FUNCTION "Gest Automatico" : VOID
TITLE =Gestione Ciclo Automatico
AUTHOR : MassimoZ
FAMILY : NovaSrl
VERSION : 0.1

BEGIN
NETWORK
TITLE =Condizioni per Ciclo

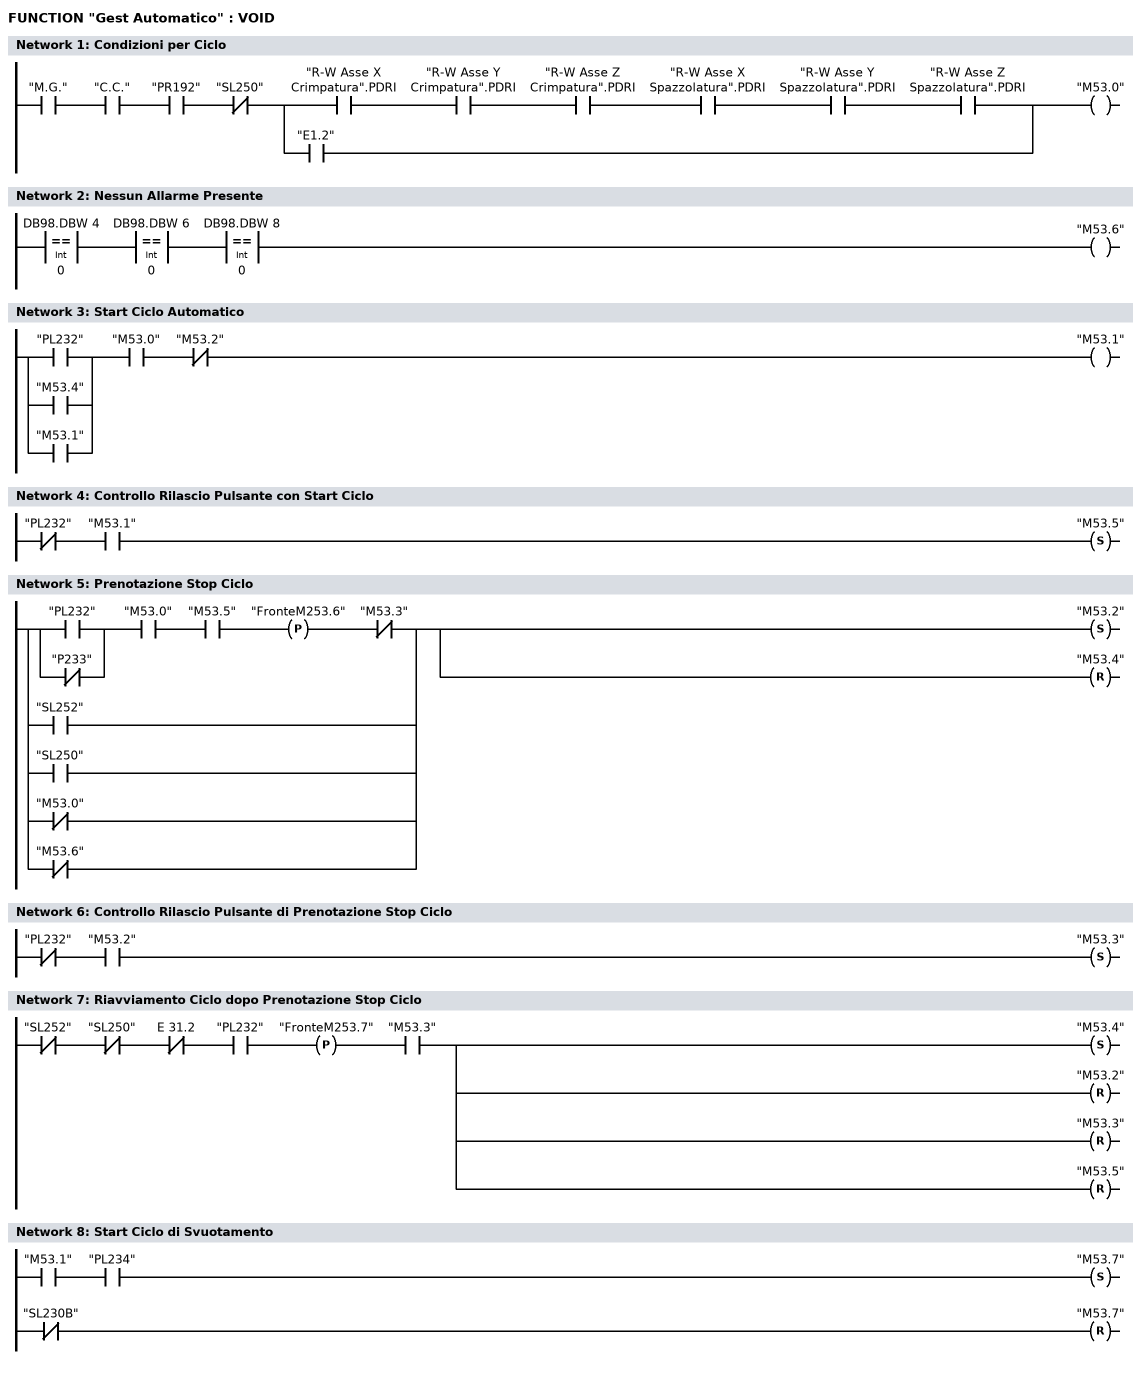
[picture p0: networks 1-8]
      U     "M.G.";
      U     "C.C.";
      U     "PR192";
      UN    "SL250";
      U(    ;
      U     "R-W Asse X Crimpatura".PDRI;
      U     "R-W Asse Y Crimpatura".PDRI;
      U     "R-W Asse Z Crimpatura".PDRI;
      U     "R-W Asse X Spazzolatura".PDRI;
      U     "R-W Asse Y Spazzolatura".PDRI;
      U     "R-W Asse Z Spazzolatura".PDRI;
      O     "E1.2";
      )     ;
      =     "M53.0";
NETWORK
TITLE =Nessun Allarme Presente

      U(    ;
      L     DB98.DBW    4;
      L     0;
      ==I   ;
      )     ;
      U(    ;
      L     DB98.DBW    6;
      L     0;
      ==I   ;
      )     ;
      U(    ;
      L     DB98.DBW    8;
      L     0;
      ==I   ;
      )     ;
      =     "M53.6";
NETWORK
TITLE =Start Ciclo Automatico

      U(    ;
      O     "PL232";
      O     "M53.4";
      O     "M53.1";
      )     ;
      U     "M53.0";
      UN    "M53.2";
      =     "M53.1";
NETWORK
TITLE =Controllo Rilascio Pulsante con Start Ciclo

      UN    "PL232";
      U     "M53.1";
      S     "M53.5";
NETWORK
TITLE =Prenotazione Stop Ciclo

      U(    ;
      O     "PL232";
      ON    "P233";
      )     ;
      U     "M53.0";
      U     "M53.5";
      FP    "FronteM253.6";
      UN    "M53.3";
      O     "SL252";
      O     "SL250";
      ON    "M53.0";
      ON    "M53.6";
      S     "M53.2";
      R     "M53.4";
NETWORK
TITLE =Controllo Rilascio Pulsante di Prenotazione Stop Ciclo

      UN    "PL232";
      U     "M53.2";
      S     "M53.3";
NETWORK
TITLE =Riavviamento Ciclo dopo Prenotazione Stop Ciclo

      UN    "SL252";
      UN    "SL250";
      UN    E     31.2;
      U     "PL232";
      FP    "FronteM253.7";
      U     "M53.3";
      S     "M53.4";
      R     "M53.2";
      R     "M53.3";
      R     "M53.5";
NETWORK
TITLE =Start Ciclo di Svuotamento

      U     "M53.1";
      U     "PL234";
      S     "M53.7";
      UN    "SL230B";
      R     "M53.7";
      NOP   0;
NETWORK
TITLE ======== Ciclo Automatico =======

NETWORK
TITLE =Presenza Pezzo in Entrata Zona Crimpatura

      U(    ;
      UN    "SL230";
      U     "SL230B";
      U     "FT183";
      L     S5T#1S500MS;
      SE    T     36;
      NOP   0;
      NOP   0;
      NOP   0;
      U     T     36;
      )     ;
      L     S5T#4S;
      SA    T     37;
      NOP   0;
      NOP   0;
      NOP   0;
      U     T     37;
      =     "M54.0";
NETWORK
TITLE =Presenza Pezzo Zona Crimpatura

      U(    ;
      UN    "SL230";
      U     "SL230B";
      U     "FT186";
      L     S5T#800MS;
      SE    T     38;
      NOP   0;
      NOP   0;
      NOP   0;
      U     T     38;
      )     ;
      L     S5T#500MS;
      SA    T     39;
      NOP   0;
      NOP   0;
      NOP   0;
      U     T     39;
      =     "M54.1";
NETWORK
TITLE =Presenza Pezzo Zona Spazzolatura

      U(    ;
      UN    "SL230";
      U     "SL230B";
      U     "FT190";
      L     S5T#800MS;
      SE    T     40;
      NOP   0;
      NOP   0;
      NOP   0;
      U     T     40;
      )     ;
      L     S5T#500MS;
      SA    T     54;
      NOP   0;
      NOP   0;
      NOP   0;
      U     T     54;
      =     "M54.2";
NETWORK
TITLE =Com Aut Start Motore Nastro Trasportatore

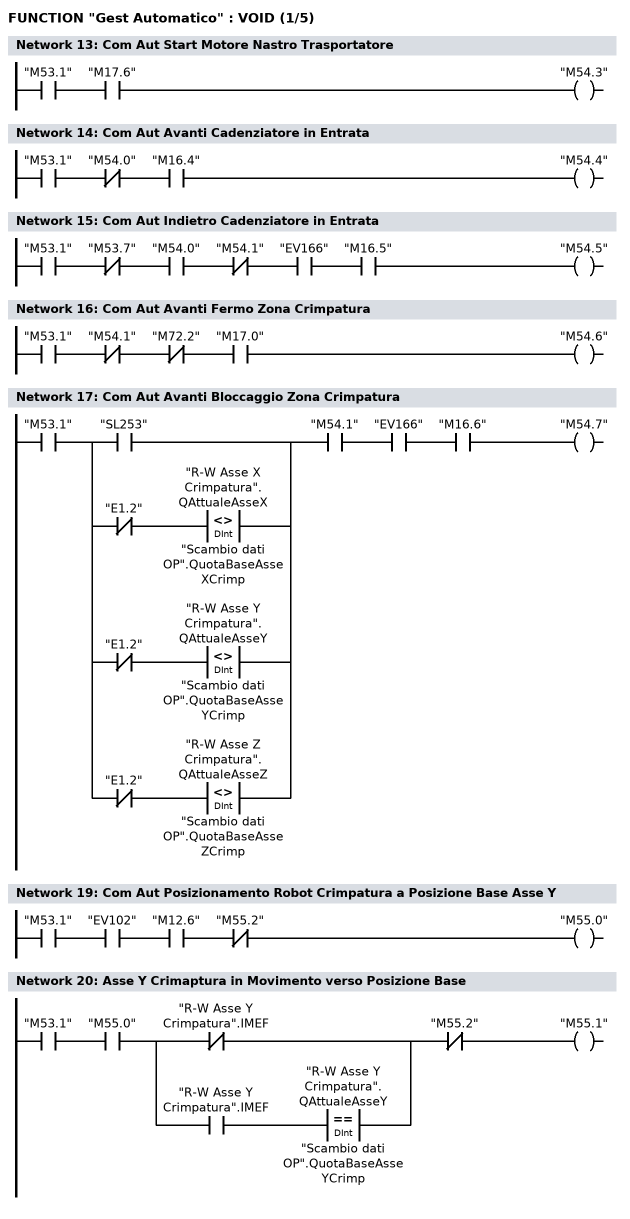
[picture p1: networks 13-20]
      U     "M53.1";
      U     "M17.6";
      =     "M54.3";
NETWORK
TITLE =Com Aut Avanti Cadenziatore in Entrata

      U     "M53.1";
      UN    "M54.0";
      U     "M16.4";
      =     "M54.4";
NETWORK
TITLE =Com Aut Indietro Cadenziatore in Entrata

      U     "M53.1";
      UN    "M53.7";
      U     "M54.0";
      UN    "M54.1";
      U     "EV166";
      U     "M16.5";
      =     "M54.5";
NETWORK
TITLE =Com Aut Avanti Fermo Zona Crimpatura

      U     "M53.1";
      UN    "M54.1";
      UN    "M72.2";
      U     "M17.0";
      =     "M54.6";
NETWORK
TITLE =Com Aut Avanti Bloccaggio Zona Crimpatura

      U     "M53.1";
      U(    ;
      O     "SL253";
      O     ;
      UN    "E1.2";
      U(    ;
      L     "R-W Asse X Crimpatura".QAttualeAsseX;
      L     "Scambio dati OP".QuotaBaseAsseXCrimp;
      <>D   ;
      )     ;
      O     ;
      UN    "E1.2";
      U(    ;
      L     "R-W Asse Y Crimpatura".QAttualeAsseY;
      L     "Scambio dati OP".QuotaBaseAsseYCrimp;
      <>D   ;
      )     ;
      O     ;
      UN    "E1.2";
      U(    ;
      L     "R-W Asse Z Crimpatura".QAttualeAsseZ;
      L     "Scambio dati OP".QuotaBaseAsseZCrimp;
      <>D   ;
      )     ;
      )     ;
      U     "M54.1";
      U     "EV166";
      U     "M16.6";
      =     "M54.7";
NETWORK
TITLE ======== Ciclo Automatico Crimpatura ========

NETWORK
TITLE =Com Aut Posizionamento Robot Crimpatura a Posizione Base Asse Y

      U     "M53.1";
      U     "EV102";
      U     "M12.6";
      UN    "M55.2";
      =     "M55.0";
NETWORK
TITLE =Asse Y Crimaptura in Movimento verso Posizione Base

      U     "M53.1";
      U     "M55.0";
      U(    ;
      ON    "R-W Asse Y Crimpatura".IMEF;
      O     ;
      U     "R-W Asse Y Crimpatura".IMEF;
      U(    ;
      L     "R-W Asse Y Crimpatura".QAttualeAsseY;
      L     "Scambio dati OP".QuotaBaseAsseYCrimp;
      ==D   ;
      )     ;
      )     ;
      UN    "M55.2";
      =     "M55.1";
NETWORK
TITLE =Asse Y Crimpatura Posizione Base Raggiunta

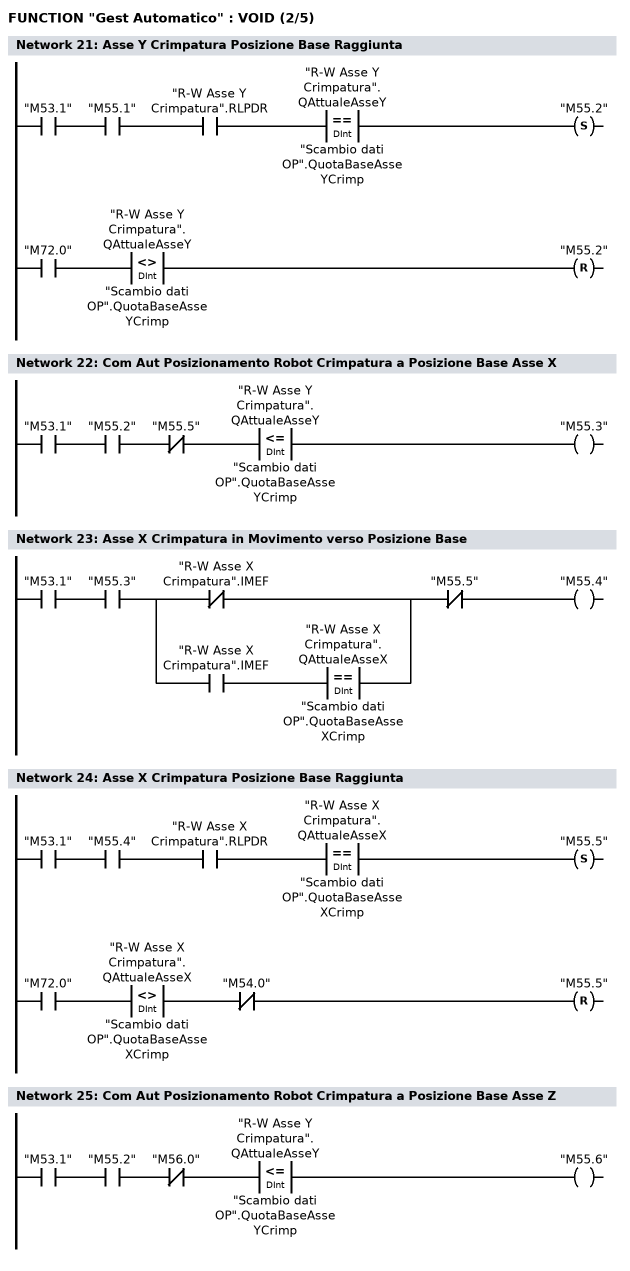
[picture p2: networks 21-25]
      U     "M53.1";
      U     "M55.1";
      U     "R-W Asse Y Crimpatura".RLPDR;
      U(    ;
      L     "R-W Asse Y Crimpatura".QAttualeAsseY;
      L     "Scambio dati OP".QuotaBaseAsseYCrimp;
      ==D   ;
      )     ;
      S     "M55.2";
      U     "M72.0";
      U(    ;
      L     "R-W Asse Y Crimpatura".QAttualeAsseY;
      L     "Scambio dati OP".QuotaBaseAsseYCrimp;
      <>D   ;
      )     ;
      R     "M55.2";
      NOP   0;
NETWORK
TITLE =Com Aut Posizionamento Robot Crimpatura a Posizione Base Asse X

      U     "M53.1";
      U     "M55.2";
      UN    "M55.5";
      U(    ;
      L     "R-W Asse Y Crimpatura".QAttualeAsseY;
      L     "Scambio dati OP".QuotaBaseAsseYCrimp;
      <=D   ;
      )     ;
      =     "M55.3";
NETWORK
TITLE =Asse X Crimpatura in Movimento verso Posizione Base

      U     "M53.1";
      U     "M55.3";
      U(    ;
      ON    "R-W Asse X Crimpatura".IMEF;
      O     ;
      U     "R-W Asse X Crimpatura".IMEF;
      U(    ;
      L     "R-W Asse X Crimpatura".QAttualeAsseX;
      L     "Scambio dati OP".QuotaBaseAsseXCrimp;
      ==D   ;
      )     ;
      )     ;
      UN    "M55.5";
      =     "M55.4";
NETWORK
TITLE =Asse X Crimpatura Posizione Base Raggiunta

      U     "M53.1";
      U     "M55.4";
      U     "R-W Asse X Crimpatura".RLPDR;
      U(    ;
      L     "R-W Asse X Crimpatura".QAttualeAsseX;
      L     "Scambio dati OP".QuotaBaseAsseXCrimp;
      ==D   ;
      )     ;
      S     "M55.5";
      U     "M72.0";
      U(    ;
      L     "R-W Asse X Crimpatura".QAttualeAsseX;
      L     "Scambio dati OP".QuotaBaseAsseXCrimp;
      <>D   ;
      )     ;
      UN    "M54.0";
      R     "M55.5";
      NOP   0;
NETWORK
TITLE =Com Aut Posizionamento Robot Crimpatura a Posizione Base Asse Z

      U     "M53.1";
      U     "M55.2";
      UN    "M56.0";
      U(    ;
      L     "R-W Asse Y Crimpatura".QAttualeAsseY;
      L     "Scambio dati OP".QuotaBaseAsseYCrimp;
      <=D   ;
      )     ;
      =     "M55.6";
NETWORK
TITLE =Asse Z Crimpatura in Movimento verso Posizione Base

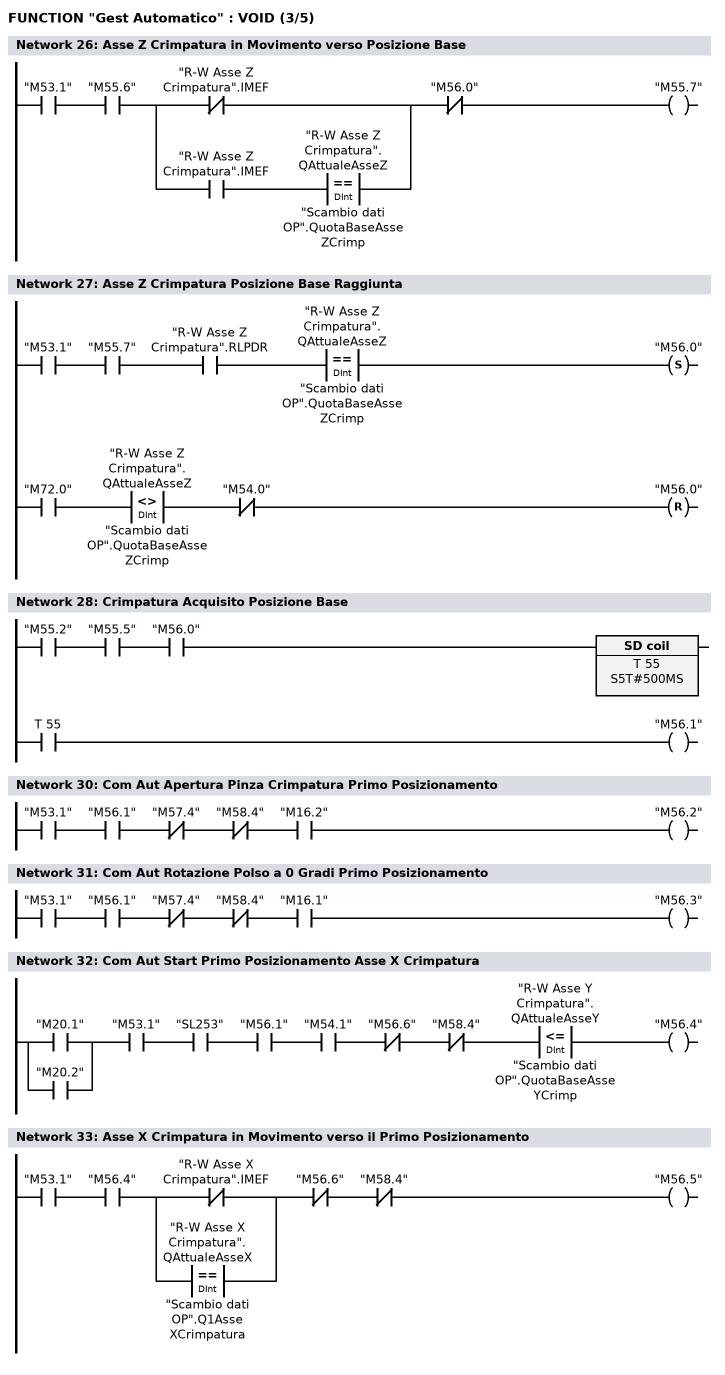
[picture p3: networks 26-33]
      U     "M53.1";
      U     "M55.6";
      U(    ;
      ON    "R-W Asse Z Crimpatura".IMEF;
      O     ;
      U     "R-W Asse Z Crimpatura".IMEF;
      U(    ;
      L     "R-W Asse Z Crimpatura".QAttualeAsseZ;
      L     "Scambio dati OP".QuotaBaseAsseZCrimp;
      ==D   ;
      )     ;
      )     ;
      UN    "M56.0";
      =     "M55.7";
NETWORK
TITLE =Asse Z Crimpatura Posizione Base Raggiunta

      U     "M53.1";
      U     "M55.7";
      U     "R-W Asse Z Crimpatura".RLPDR;
      U(    ;
      L     "R-W Asse Z Crimpatura".QAttualeAsseZ;
      L     "Scambio dati OP".QuotaBaseAsseZCrimp;
      ==D   ;
      )     ;
      S     "M56.0";
      U     "M72.0";
      U(    ;
      L     "R-W Asse Z Crimpatura".QAttualeAsseZ;
      L     "Scambio dati OP".QuotaBaseAsseZCrimp;
      <>D   ;
      )     ;
      UN    "M54.0";
      R     "M56.0";
      NOP   0;
NETWORK
TITLE =Crimpatura Acquisito Posizione Base

      U     "M55.2";
      U     "M55.5";
      U     "M56.0";
      L     S5T#500MS;
      SE    T     55;
      NOP   0;
      NOP   0;
      NOP   0;
      U     T     55;
      =     "M56.1";
NETWORK
TITLE ======== Primo Posizionamento Crimpatura =======

NETWORK
TITLE =Com Aut Apertura Pinza Crimpatura Primo Posizionamento

      U     "M53.1";
      U     "M56.1";
      UN    "M57.4";
      UN    "M58.4";
      U     "M16.2";
      =     "M56.2";
NETWORK
TITLE =Com Aut Rotazione Polso a 0 Gradi Primo Posizionamento

      U     "M53.1";
      U     "M56.1";
      UN    "M57.4";
      UN    "M58.4";
      U     "M16.1";
      =     "M56.3";
NETWORK
TITLE =Com Aut Start Primo Posizionamento Asse X Crimpatura

      U(    ;
      O     "M20.1";
      O     "M20.2";
      )     ;
      U     "M53.1";
      U     "SL253";
      U     "M56.1";
      U     "M54.1";
      UN    "M56.6";
      UN    "M58.4";
      U(    ;
      L     "R-W Asse Y Crimpatura".QAttualeAsseY;
      L     "Scambio dati OP".QuotaBaseAsseYCrimp;
      <=D   ;
      )     ;
      =     "M56.4";
NETWORK
TITLE =Asse X Crimpatura in Movimento verso il Primo Posizionamento

      U     "M53.1";
      U     "M56.4";
      U(    ;
      ON    "R-W Asse X Crimpatura".IMEF;
      O(    ;
      L     "R-W Asse X Crimpatura".QAttualeAsseX;
      L     "Scambio dati OP".Q1AsseXCrimpatura;
      ==D   ;
      )     ;
      )     ;
      UN    "M56.6";
      UN    "M58.4";
      =     "M56.5";
NETWORK
TITLE =Asse X Crimpatura Primo Posizionamento Raggiunto

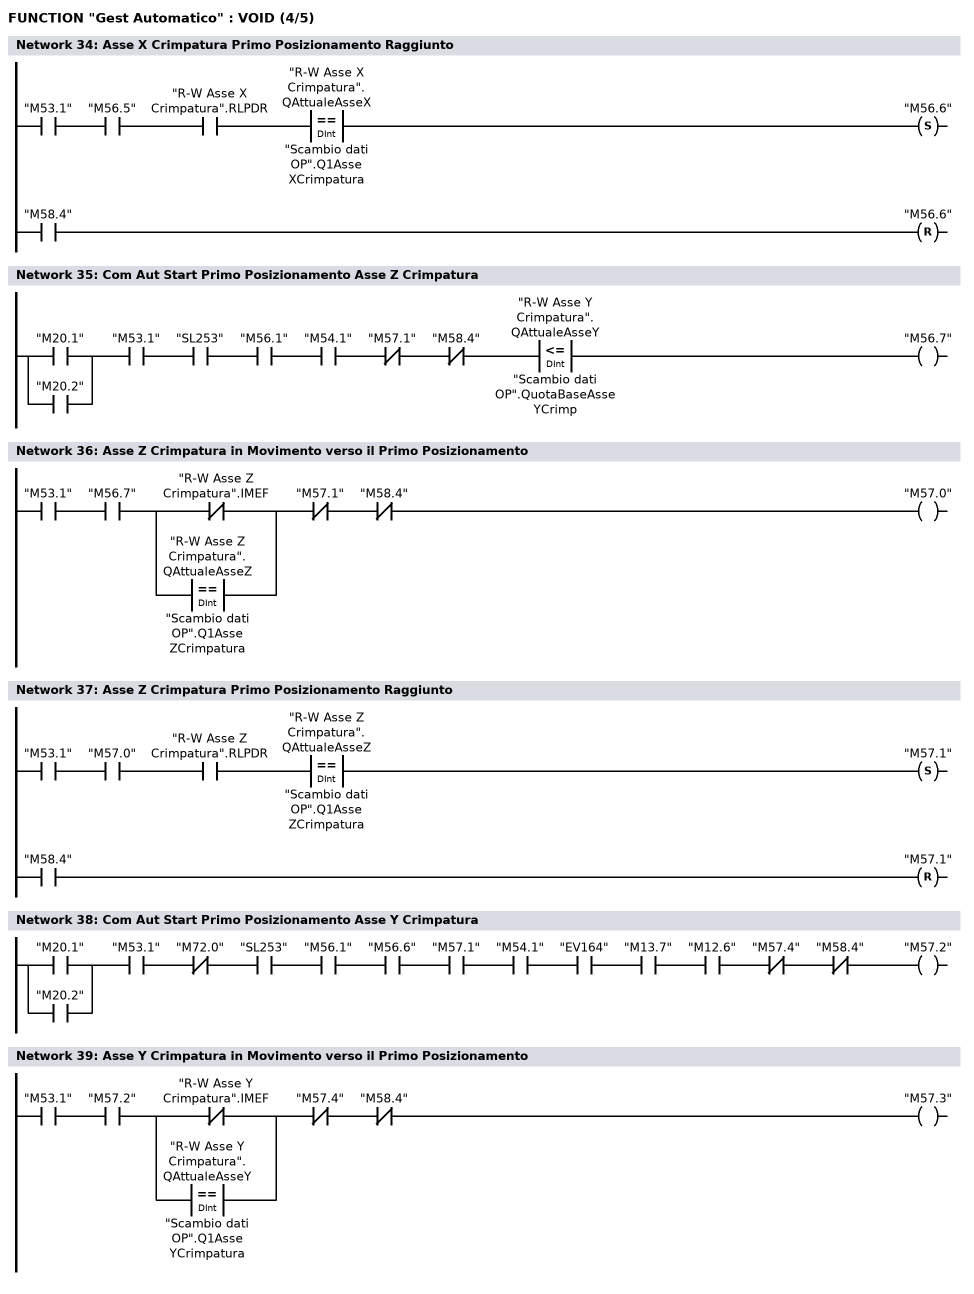
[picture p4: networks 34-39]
      U     "M53.1";
      U     "M56.5";
      U     "R-W Asse X Crimpatura".RLPDR;
      U(    ;
      L     "R-W Asse X Crimpatura".QAttualeAsseX;
      L     "Scambio dati OP".Q1AsseXCrimpatura;
      ==D   ;
      )     ;
      S     "M56.6";
      U     "M58.4";
      R     "M56.6";
      NOP   0;
NETWORK
TITLE =Com Aut Start Primo Posizionamento Asse Z Crimpatura

      U(    ;
      O     "M20.1";
      O     "M20.2";
      )     ;
      U     "M53.1";
      U     "SL253";
      U     "M56.1";
      U     "M54.1";
      UN    "M57.1";
      UN    "M58.4";
      U(    ;
      L     "R-W Asse Y Crimpatura".QAttualeAsseY;
      L     "Scambio dati OP".QuotaBaseAsseYCrimp;
      <=D   ;
      )     ;
      =     "M56.7";
NETWORK
TITLE =Asse Z Crimpatura in Movimento verso il Primo Posizionamento

      U     "M53.1";
      U     "M56.7";
      U(    ;
      ON    "R-W Asse Z Crimpatura".IMEF;
      O(    ;
      L     "R-W Asse Z Crimpatura".QAttualeAsseZ;
      L     "Scambio dati OP".Q1AsseZCrimpatura;
      ==D   ;
      )     ;
      )     ;
      UN    "M57.1";
      UN    "M58.4";
      =     "M57.0";
NETWORK
TITLE =Asse Z Crimpatura Primo Posizionamento Raggiunto

      U     "M53.1";
      U     "M57.0";
      U     "R-W Asse Z Crimpatura".RLPDR;
      U(    ;
      L     "R-W Asse Z Crimpatura".QAttualeAsseZ;
      L     "Scambio dati OP".Q1AsseZCrimpatura;
      ==D   ;
      )     ;
      S     "M57.1";
      U     "M58.4";
      R     "M57.1";
      NOP   0;
NETWORK
TITLE =Com Aut Start Primo Posizionamento Asse Y Crimpatura

      U(    ;
      O     "M20.1";
      O     "M20.2";
      )     ;
      U     "M53.1";
      UN    "M72.0";
      U     "SL253";
      U     "M56.1";
      U     "M56.6";
      U     "M57.1";
      U     "M54.1";
      U     "EV164";
      U     "M13.7";
      U     "M12.6";
      UN    "M57.4";
      UN    "M58.4";
      =     "M57.2";
NETWORK
TITLE =Asse Y Crimpatura in Movimento verso il Primo Posizionamento

      U     "M53.1";
      U     "M57.2";
      U(    ;
      ON    "R-W Asse Y Crimpatura".IMEF;
      O(    ;
      L     "R-W Asse Y Crimpatura".QAttualeAsseY;
      L     "Scambio dati OP".Q1AsseYCrimpatura;
      ==D   ;
      )     ;
      )     ;
      UN    "M57.4";
      UN    "M58.4";
      =     "M57.3";
NETWORK
TITLE =Asse Y Crimpatura Primo Posizionamento Raggiunto

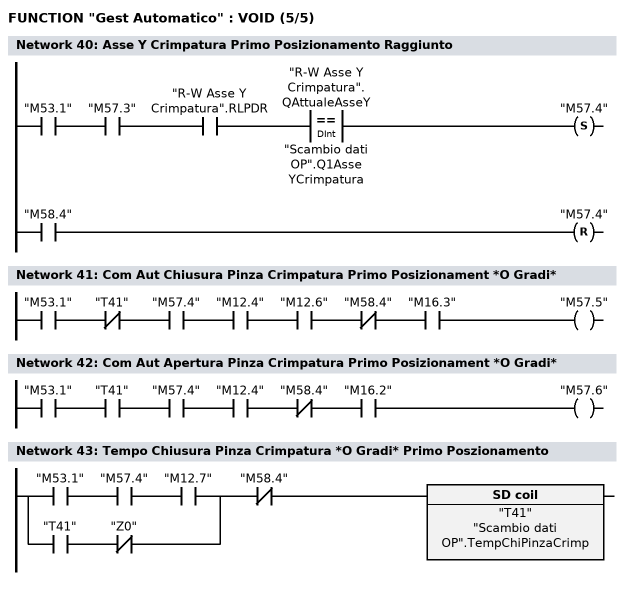
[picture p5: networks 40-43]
      U     "M53.1";
      U     "M57.3";
      U     "R-W Asse Y Crimpatura".RLPDR;
      U(    ;
      L     "R-W Asse Y Crimpatura".QAttualeAsseY;
      L     "Scambio dati OP".Q1AsseYCrimpatura;
      ==D   ;
      )     ;
      S     "M57.4";
      U     "M58.4";
      R     "M57.4";
      NOP   0;
NETWORK
TITLE =Com Aut Chiusura Pinza Crimpatura Primo Posizionament *O Gradi*

      U     "M53.1";
      UN    "T41";
      U     "M57.4";
      U     "M12.4";
      U     "M12.6";
      UN    "M58.4";
      U     "M16.3";
      =     "M57.5";
NETWORK
TITLE =Com Aut Apertura Pinza Crimpatura Primo Posizionament *O Gradi*

      U     "M53.1";
      U     "T41";
      U     "M57.4";
      U     "M12.4";
      UN    "M58.4";
      U     "M16.2";
      =     "M57.6";
NETWORK
TITLE =Tempo Chiusura Pinza Crimpatura *O Gradi* Primo Poszionamento

      U(    ;
      U     "M53.1";
      U     "M57.4";
      U     "M12.7";
      O     ;
      U     "T41";
      UN    "Z0";
      )     ;
      UN    "M58.4";
      L     "Scambio dati OP".TempChiPinzaCrimp;
      SE    "T41";
      NOP   0;
      NOP   0;
      NOP   0;
      NOP   0;
NETWORK
TITLE =Numero di Crimpate da Eseguire *O Gradi* Primo Posizionamento

      U     "EV103";
      U     "M57.5";
      U     "M12.4";
      UN    "M58.4";
      ZR    "Z0";
      BLD   101;
      U     "M57.2";
      L     "Scambio dati OP".NCrimp0Gradi;
      S     "Z0";
      U     "M58.4";
      R     "Z0";
      NOP   0;
      NOP   0;
      NOP   0;
NETWORK
TITLE =Com Aut Rotazione Polso a 45 Gradi Primo Posizionamento

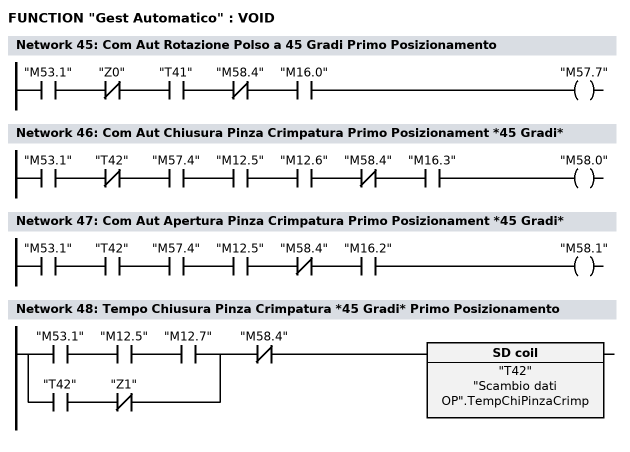
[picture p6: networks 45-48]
      U     "M53.1";
      UN    "Z0";
      U     "T41";
      UN    "M58.4";
      U     "M16.0";
      =     "M57.7";
NETWORK
TITLE =Com Aut Chiusura Pinza Crimpatura Primo Posizionament *45 Gradi*

      U     "M53.1";
      UN    "T42";
      U     "M57.4";
      U     "M12.5";
      U     "M12.6";
      UN    "M58.4";
      U     "M16.3";
      =     "M58.0";
NETWORK
TITLE =Com Aut Apertura Pinza Crimpatura Primo Posizionament *45 Gradi*

      U     "M53.1";
      U     "T42";
      U     "M57.4";
      U     "M12.5";
      UN    "M58.4";
      U     "M16.2";
      =     "M58.1";
NETWORK
TITLE =Tempo Chiusura Pinza Crimpatura *45 Gradi* Primo Posizionamento

      U(    ;
      U     "M53.1";
      U     "M12.5";
      U     "M12.7";
      O     ;
      U     "T42";
      UN    "Z1";
      )     ;
      UN    "M58.4";
      L     "Scambio dati OP".TempChiPinzaCrimp;
      SE    "T42";
      NOP   0;
      NOP   0;
      NOP   0;
      NOP   0;
NETWORK
TITLE =Numero di Crimpate da Eseguire *45 Gradi* Primo Posizionamento

      U     "EV103";
      U     "M58.0";
      U     "M12.5";
      UN    "M58.4";
      ZR    "Z1";
      BLD   101;
      U     "M57.2";
      L     "Scambio dati OP".NCrimp45Gradi;
      S     "Z1";
      U     "M58.4";
      R     "Z1";
      NOP   0;
      NOP   0;
      NOP   0;
NETWORK
TITLE =Com Aut Start Pos Base Asse Y Crimpatura dopo Prima Crimpatura

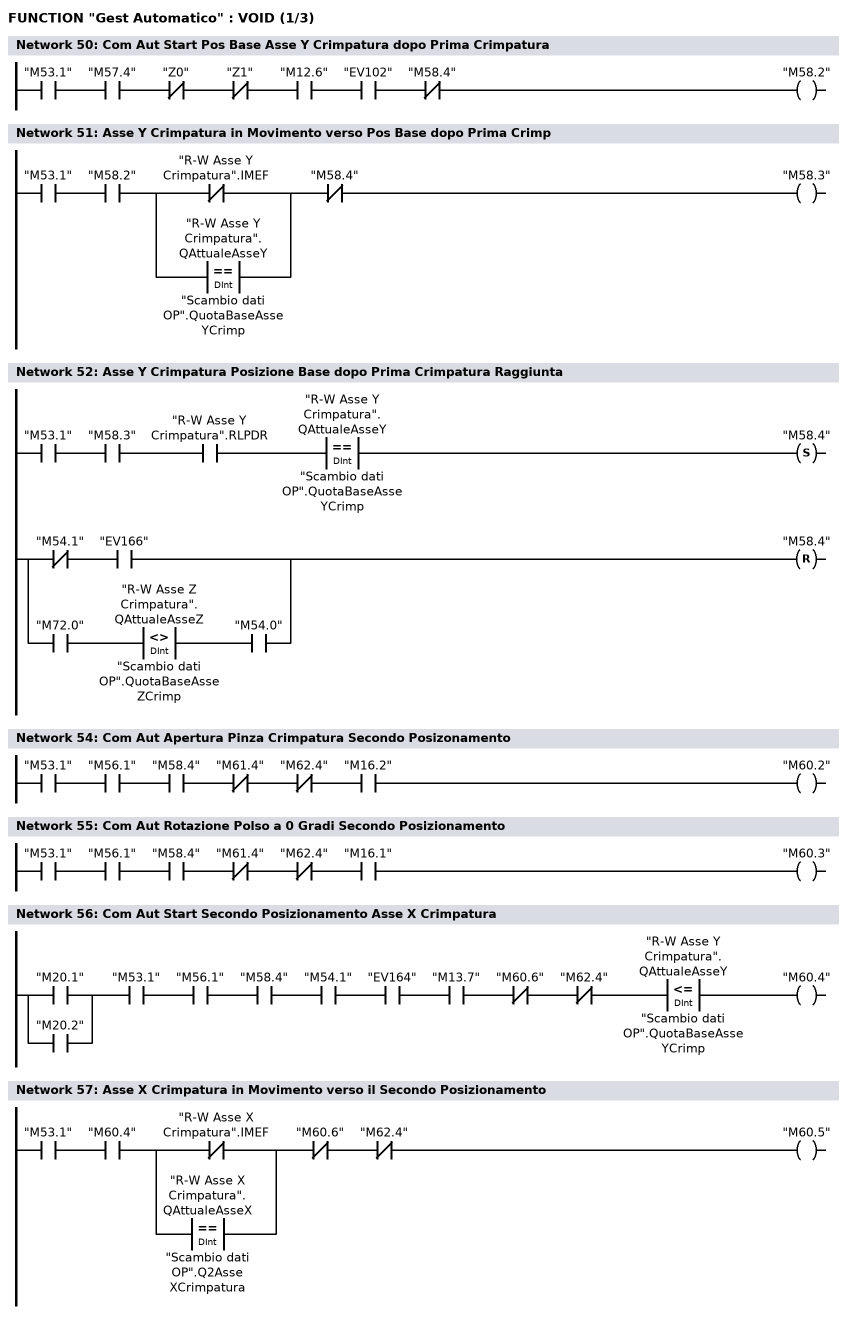
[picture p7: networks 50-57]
      U     "M53.1";
      U     "M57.4";
      UN    "Z0";
      UN    "Z1";
      U     "M12.6";
      U     "EV102";
      UN    "M58.4";
      =     "M58.2";
NETWORK
TITLE =Asse Y Crimpatura in Movimento verso Pos Base dopo Prima Crimp

      U     "M53.1";
      U     "M58.2";
      U(    ;
      ON    "R-W Asse Y Crimpatura".IMEF;
      O(    ;
      L     "R-W Asse Y Crimpatura".QAttualeAsseY;
      L     "Scambio dati OP".QuotaBaseAsseYCrimp;
      ==D   ;
      )     ;
      )     ;
      UN    "M58.4";
      =     "M58.3";
NETWORK
TITLE =Asse Y Crimpatura Posizione Base dopo Prima Crimpatura Raggiunta

      U     "M53.1";
      U     "M58.3";
      U     "R-W Asse Y Crimpatura".RLPDR;
      U(    ;
      L     "R-W Asse Y Crimpatura".QAttualeAsseY;
      L     "Scambio dati OP".QuotaBaseAsseYCrimp;
      ==D   ;
      )     ;
      S     "M58.4";
      U(    ;
      UN    "M54.1";
      U     "EV166";
      O     ;
      U     "M72.0";
      U(    ;
      L     "R-W Asse Z Crimpatura".QAttualeAsseZ;
      L     "Scambio dati OP".QuotaBaseAsseZCrimp;
      <>D   ;
      )     ;
      U     "M54.0";
      )     ;
      R     "M58.4";
      NOP   0;
NETWORK
TITLE ======== Secondo Posizionamento Crimpatura =======

NETWORK
TITLE =Com Aut Apertura Pinza Crimpatura Secondo Posizonamento

      U     "M53.1";
      U     "M56.1";
      U     "M58.4";
      UN    "M61.4";
      UN    "M62.4";
      U     "M16.2";
      =     "M60.2";
NETWORK
TITLE =Com Aut Rotazione Polso a 0 Gradi Secondo Posizionamento

      U     "M53.1";
      U     "M56.1";
      U     "M58.4";
      UN    "M61.4";
      UN    "M62.4";
      U     "M16.1";
      =     "M60.3";
NETWORK
TITLE =Com Aut Start Secondo Posizionamento Asse X Crimpatura

      U(    ;
      O     "M20.1";
      O     "M20.2";
      )     ;
      U     "M53.1";
      U     "M56.1";
      U     "M58.4";
      U     "M54.1";
      U     "EV164";
      U     "M13.7";
      UN    "M60.6";
      UN    "M62.4";
      U(    ;
      L     "R-W Asse Y Crimpatura".QAttualeAsseY;
      L     "Scambio dati OP".QuotaBaseAsseYCrimp;
      <=D   ;
      )     ;
      =     "M60.4";
NETWORK
TITLE =Asse X Crimpatura in Movimento verso il Secondo Posizionamento

      U     "M53.1";
      U     "M60.4";
      U(    ;
      ON    "R-W Asse X Crimpatura".IMEF;
      O(    ;
      L     "R-W Asse X Crimpatura".QAttualeAsseX;
      L     "Scambio dati OP".Q2AsseXCrimpatura;
      ==D   ;
      )     ;
      )     ;
      UN    "M60.6";
      UN    "M62.4";
      =     "M60.5";
NETWORK
TITLE =Asse X Crimpatura Secondo Posizionamento Raggiunto

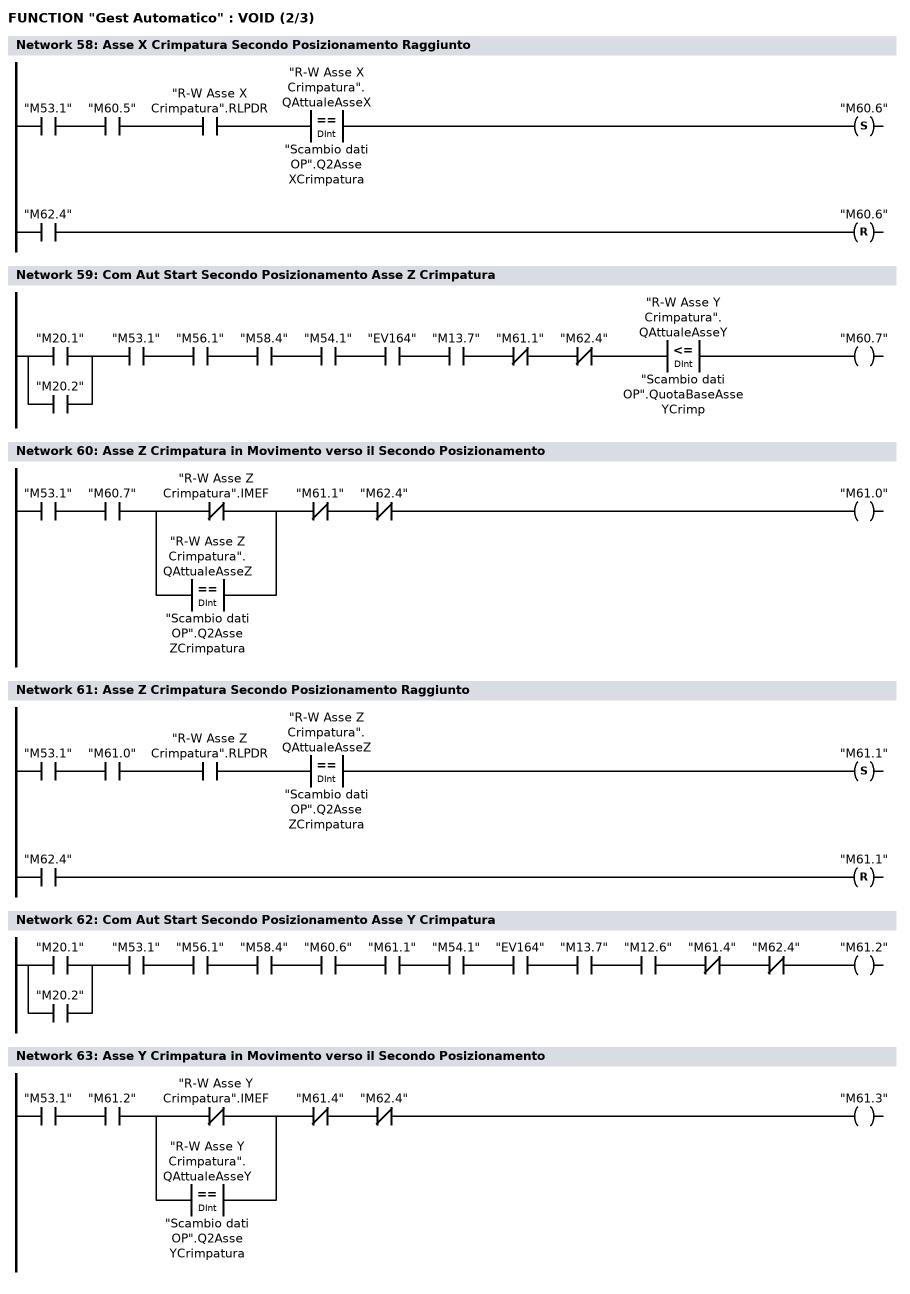
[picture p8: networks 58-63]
      U     "M53.1";
      U     "M60.5";
      U     "R-W Asse X Crimpatura".RLPDR;
      U(    ;
      L     "R-W Asse X Crimpatura".QAttualeAsseX;
      L     "Scambio dati OP".Q2AsseXCrimpatura;
      ==D   ;
      )     ;
      S     "M60.6";
      U     "M62.4";
      R     "M60.6";
      NOP   0;
NETWORK
TITLE =Com Aut Start Secondo Posizionamento Asse Z Crimpatura

      U(    ;
      O     "M20.1";
      O     "M20.2";
      )     ;
      U     "M53.1";
      U     "M56.1";
      U     "M58.4";
      U     "M54.1";
      U     "EV164";
      U     "M13.7";
      UN    "M61.1";
      UN    "M62.4";
      U(    ;
      L     "R-W Asse Y Crimpatura".QAttualeAsseY;
      L     "Scambio dati OP".QuotaBaseAsseYCrimp;
      <=D   ;
      )     ;
      =     "M60.7";
NETWORK
TITLE =Asse Z Crimpatura in Movimento verso il Secondo Posizionamento

      U     "M53.1";
      U     "M60.7";
      U(    ;
      ON    "R-W Asse Z Crimpatura".IMEF;
      O(    ;
      L     "R-W Asse Z Crimpatura".QAttualeAsseZ;
      L     "Scambio dati OP".Q2AsseZCrimpatura;
      ==D   ;
      )     ;
      )     ;
      UN    "M61.1";
      UN    "M62.4";
      =     "M61.0";
NETWORK
TITLE =Asse Z Crimpatura Secondo Posizionamento Raggiunto

      U     "M53.1";
      U     "M61.0";
      U     "R-W Asse Z Crimpatura".RLPDR;
      U(    ;
      L     "R-W Asse Z Crimpatura".QAttualeAsseZ;
      L     "Scambio dati OP".Q2AsseZCrimpatura;
      ==D   ;
      )     ;
      S     "M61.1";
      U     "M62.4";
      R     "M61.1";
      NOP   0;
NETWORK
TITLE =Com Aut Start Secondo Posizionamento Asse Y Crimpatura

      U(    ;
      O     "M20.1";
      O     "M20.2";
      )     ;
      U     "M53.1";
      U     "M56.1";
      U     "M58.4";
      U     "M60.6";
      U     "M61.1";
      U     "M54.1";
      U     "EV164";
      U     "M13.7";
      U     "M12.6";
      UN    "M61.4";
      UN    "M62.4";
      =     "M61.2";
NETWORK
TITLE =Asse Y Crimpatura in Movimento verso il Secondo Posizionamento

      U     "M53.1";
      U     "M61.2";
      U(    ;
      ON    "R-W Asse Y Crimpatura".IMEF;
      O(    ;
      L     "R-W Asse Y Crimpatura".QAttualeAsseY;
      L     "Scambio dati OP".Q2AsseYCrimpatura;
      ==D   ;
      )     ;
      )     ;
      UN    "M61.4";
      UN    "M62.4";
      =     "M61.3";
NETWORK
TITLE =Asse Y Crimpatura Secondo Posizionamento Raggiunto

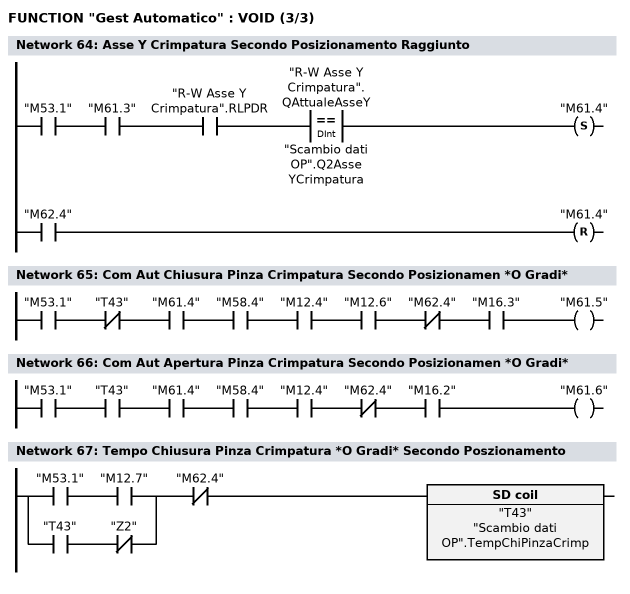
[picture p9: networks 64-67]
      U     "M53.1";
      U     "M61.3";
      U     "R-W Asse Y Crimpatura".RLPDR;
      U(    ;
      L     "R-W Asse Y Crimpatura".QAttualeAsseY;
      L     "Scambio dati OP".Q2AsseYCrimpatura;
      ==D   ;
      )     ;
      S     "M61.4";
      U     "M62.4";
      R     "M61.4";
      NOP   0;
NETWORK
TITLE =Com Aut Chiusura Pinza Crimpatura Secondo Posizionamen *O Gradi*

      U     "M53.1";
      UN    "T43";
      U     "M61.4";
      U     "M58.4";
      U     "M12.4";
      U     "M12.6";
      UN    "M62.4";
      U     "M16.3";
      =     "M61.5";
NETWORK
TITLE =Com Aut Apertura Pinza Crimpatura Secondo Posizionamen *O Gradi*

      U     "M53.1";
      U     "T43";
      U     "M61.4";
      U     "M58.4";
      U     "M12.4";
      UN    "M62.4";
      U     "M16.2";
      =     "M61.6";
NETWORK
TITLE =Tempo Chiusura Pinza Crimpatura *O Gradi* Secondo Poszionamento

      U(    ;
      U     "M53.1";
      U     "M12.7";
      O     ;
      U     "T43";
      UN    "Z2";
      )     ;
      UN    "M62.4";
      L     "Scambio dati OP".TempChiPinzaCrimp;
      SE    "T43";
      NOP   0;
      NOP   0;
      NOP   0;
      NOP   0;
NETWORK
TITLE =Numero di Crimpate da Eseguire *O Gradi* Secondo Poszionamento

      U     "EV103";
      U     "M61.5";
      U     "M12.4";
      U     "M58.4";
      UN    "M62.4";
      ZR    "Z2";
      BLD   101;
      U     "M61.2";
      L     "Scambio dati OP".NCrimp0Gradi;
      S     "Z2";
      U     "M62.4";
      R     "Z2";
      NOP   0;
      NOP   0;
      NOP   0;
NETWORK
TITLE =Com Aut Rotazione Polso a 45 Gradi Secondo Posizionamento

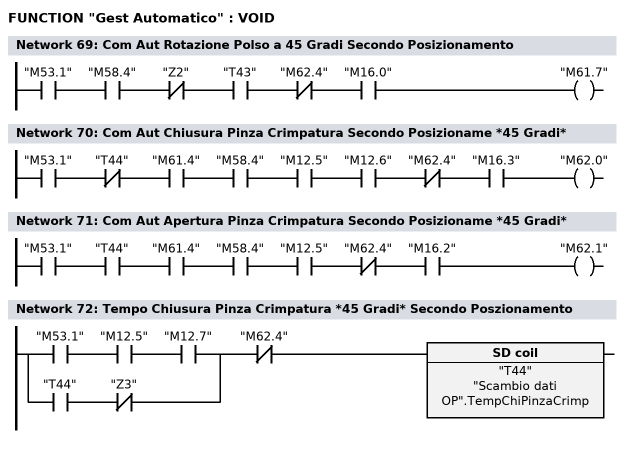
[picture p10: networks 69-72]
      U     "M53.1";
      U     "M58.4";
      UN    "Z2";
      U     "T43";
      UN    "M62.4";
      U     "M16.0";
      =     "M61.7";
NETWORK
TITLE =Com Aut Chiusura Pinza Crimpatura Secondo Posizioname *45 Gradi*

      U     "M53.1";
      UN    "T44";
      U     "M61.4";
      U     "M58.4";
      U     "M12.5";
      U     "M12.6";
      UN    "M62.4";
      U     "M16.3";
      =     "M62.0";
NETWORK
TITLE =Com Aut Apertura Pinza Crimpatura Secondo Posizioname *45 Gradi*

      U     "M53.1";
      U     "T44";
      U     "M61.4";
      U     "M58.4";
      U     "M12.5";
      UN    "M62.4";
      U     "M16.2";
      =     "M62.1";
NETWORK
TITLE =Tempo Chiusura Pinza Crimpatura *45 Gradi* Secondo Poszionamento

      U(    ;
      U     "M53.1";
      U     "M12.5";
      U     "M12.7";
      O     ;
      U     "T44";
      UN    "Z3";
      )     ;
      UN    "M62.4";
      L     "Scambio dati OP".TempChiPinzaCrimp;
      SE    "T44";
      NOP   0;
      NOP   0;
      NOP   0;
      NOP   0;
NETWORK
TITLE =Numero di Crimpate da Eseguire *45 Gradi* Secondo Posizonamento

      U     "EV103";
      U     "M62.0";
      U     "M12.5";
      U     "M58.4";
      UN    "M62.4";
      ZR    "Z3";
      BLD   101;
      U     "M61.2";
      L     "Scambio dati OP".NCrimp45Gradi;
      S     "Z3";
      U     "M62.4";
      R     "Z3";
      NOP   0;
      NOP   0;
      NOP   0;
NETWORK
TITLE =Com Aut Start Pos Base Asse Y Crimpatura dopo Seconda Crimpatura
//Inserito T69 per ritardare risalita dopo seconda crimpatura
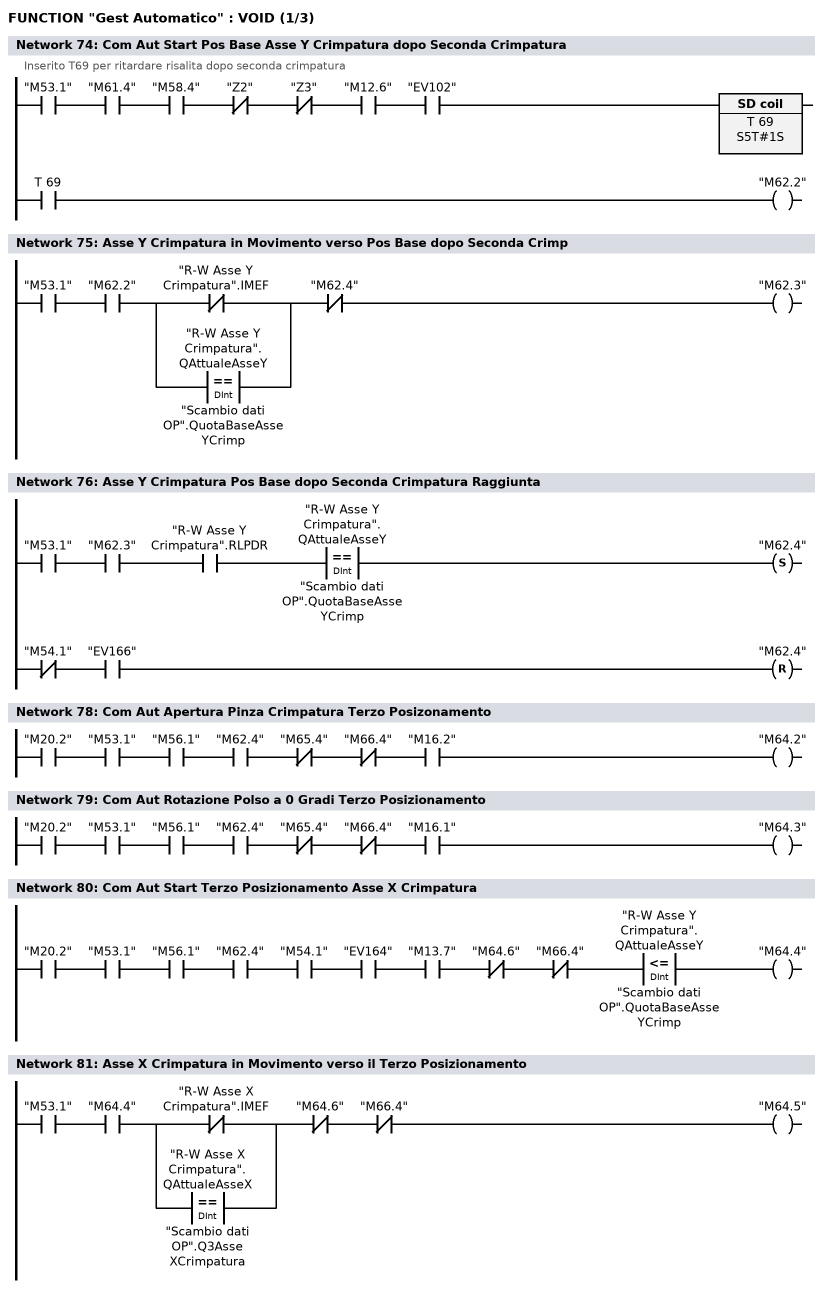
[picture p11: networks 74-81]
      U     "M53.1";
      U     "M61.4";
      U     "M58.4";
      UN    "Z2";
      UN    "Z3";
      U     "M12.6";
      U     "EV102";
      L     S5T#1S;
      SE    T     69;
      NOP   0;
      NOP   0;
      NOP   0;
      U     T     69;
      =     "M62.2";
NETWORK
TITLE =Asse Y Crimpatura in Movimento verso Pos Base dopo Seconda Crimp

      U     "M53.1";
      U     "M62.2";
      U(    ;
      ON    "R-W Asse Y Crimpatura".IMEF;
      O(    ;
      L     "R-W Asse Y Crimpatura".QAttualeAsseY;
      L     "Scambio dati OP".QuotaBaseAsseYCrimp;
      ==D   ;
      )     ;
      )     ;
      UN    "M62.4";
      =     "M62.3";
NETWORK
TITLE =Asse Y Crimpatura Pos Base dopo Seconda Crimpatura Raggiunta

      U     "M53.1";
      U     "M62.3";
      U     "R-W Asse Y Crimpatura".RLPDR;
      U(    ;
      L     "R-W Asse Y Crimpatura".QAttualeAsseY;
      L     "Scambio dati OP".QuotaBaseAsseYCrimp;
      ==D   ;
      )     ;
      S     "M62.4";
      UN    "M54.1";
      U     "EV166";
      R     "M62.4";
      NOP   0;
NETWORK
TITLE ======== Terzo Posizionamento Crimpatura =======

NETWORK
TITLE =Com Aut Apertura Pinza Crimpatura Terzo Posizonamento

      U     "M20.2";
      U     "M53.1";
      U     "M56.1";
      U     "M62.4";
      UN    "M65.4";
      UN    "M66.4";
      U     "M16.2";
      =     "M64.2";
NETWORK
TITLE =Com Aut Rotazione Polso a 0 Gradi Terzo Posizionamento

      U     "M20.2";
      U     "M53.1";
      U     "M56.1";
      U     "M62.4";
      UN    "M65.4";
      UN    "M66.4";
      U     "M16.1";
      =     "M64.3";
NETWORK
TITLE =Com Aut Start Terzo Posizionamento Asse X Crimpatura

      U     "M20.2";
      U     "M53.1";
      U     "M56.1";
      U     "M62.4";
      U     "M54.1";
      U     "EV164";
      U     "M13.7";
      UN    "M64.6";
      UN    "M66.4";
      U(    ;
      L     "R-W Asse Y Crimpatura".QAttualeAsseY;
      L     "Scambio dati OP".QuotaBaseAsseYCrimp;
      <=D   ;
      )     ;
      =     "M64.4";
NETWORK
TITLE =Asse X Crimpatura in Movimento verso il Terzo Posizionamento

      U     "M53.1";
      U     "M64.4";
      U(    ;
      ON    "R-W Asse X Crimpatura".IMEF;
      O(    ;
      L     "R-W Asse X Crimpatura".QAttualeAsseX;
      L     "Scambio dati OP".Q3AsseXCrimpatura;
      ==D   ;
      )     ;
      )     ;
      UN    "M64.6";
      UN    "M66.4";
      =     "M64.5";
NETWORK
TITLE =Asse X Crimpatura Terzo Posizionamento Raggiunto

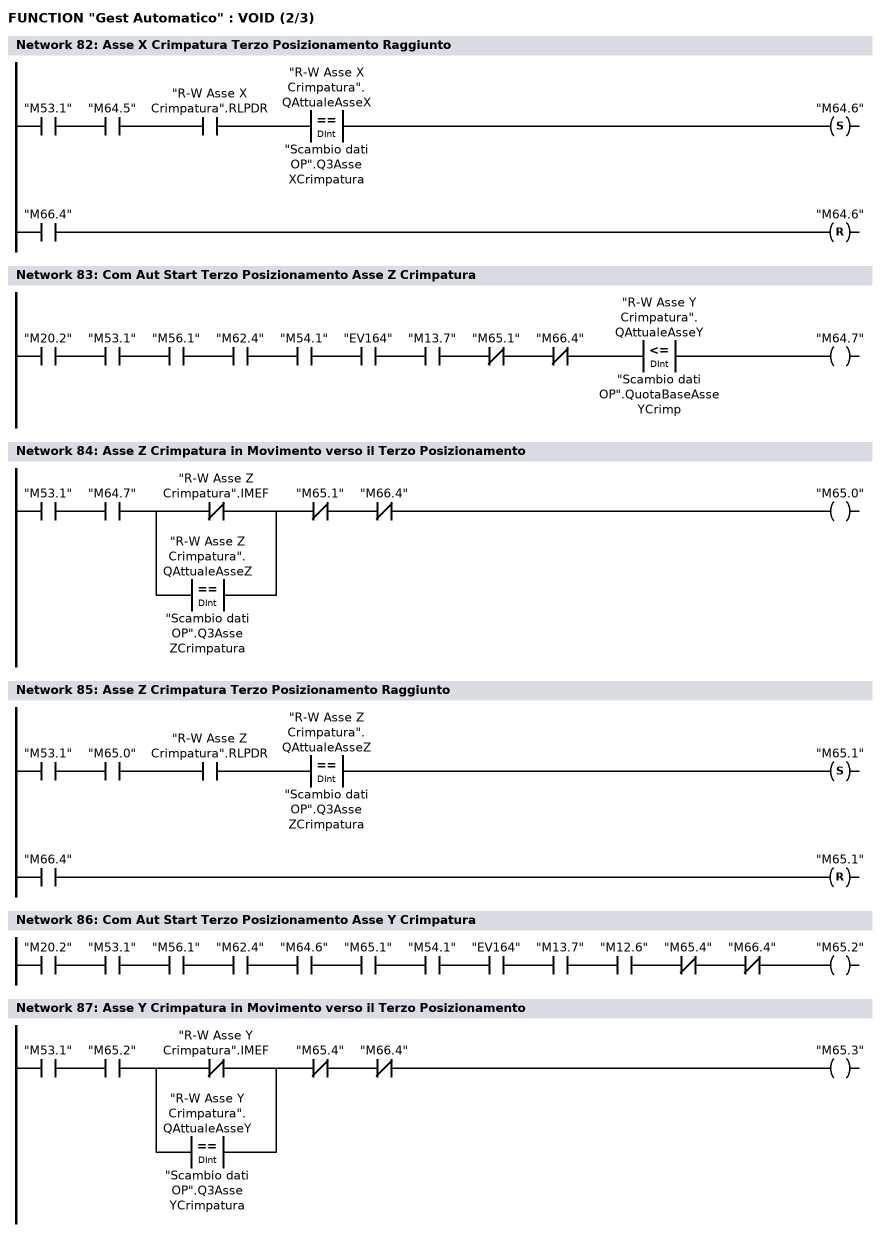
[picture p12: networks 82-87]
      U     "M53.1";
      U     "M64.5";
      U     "R-W Asse X Crimpatura".RLPDR;
      U(    ;
      L     "R-W Asse X Crimpatura".QAttualeAsseX;
      L     "Scambio dati OP".Q3AsseXCrimpatura;
      ==D   ;
      )     ;
      S     "M64.6";
      U     "M66.4";
      R     "M64.6";
      NOP   0;
NETWORK
TITLE =Com Aut Start Terzo Posizionamento Asse Z Crimpatura

      U     "M20.2";
      U     "M53.1";
      U     "M56.1";
      U     "M62.4";
      U     "M54.1";
      U     "EV164";
      U     "M13.7";
      UN    "M65.1";
      UN    "M66.4";
      U(    ;
      L     "R-W Asse Y Crimpatura".QAttualeAsseY;
      L     "Scambio dati OP".QuotaBaseAsseYCrimp;
      <=D   ;
      )     ;
      =     "M64.7";
NETWORK
TITLE =Asse Z Crimpatura in Movimento verso il Terzo Posizionamento

      U     "M53.1";
      U     "M64.7";
      U(    ;
      ON    "R-W Asse Z Crimpatura".IMEF;
      O(    ;
      L     "R-W Asse Z Crimpatura".QAttualeAsseZ;
      L     "Scambio dati OP".Q3AsseZCrimpatura;
      ==D   ;
      )     ;
      )     ;
      UN    "M65.1";
      UN    "M66.4";
      =     "M65.0";
NETWORK
TITLE =Asse Z Crimpatura Terzo Posizionamento Raggiunto

      U     "M53.1";
      U     "M65.0";
      U     "R-W Asse Z Crimpatura".RLPDR;
      U(    ;
      L     "R-W Asse Z Crimpatura".QAttualeAsseZ;
      L     "Scambio dati OP".Q3AsseZCrimpatura;
      ==D   ;
      )     ;
      S     "M65.1";
      U     "M66.4";
      R     "M65.1";
      NOP   0;
NETWORK
TITLE =Com Aut Start Terzo Posizionamento Asse Y Crimpatura

      U     "M20.2";
      U     "M53.1";
      U     "M56.1";
      U     "M62.4";
      U     "M64.6";
      U     "M65.1";
      U     "M54.1";
      U     "EV164";
      U     "M13.7";
      U     "M12.6";
      UN    "M65.4";
      UN    "M66.4";
      =     "M65.2";
NETWORK
TITLE =Asse Y Crimpatura in Movimento verso il Terzo Posizionamento

      U     "M53.1";
      U     "M65.2";
      U(    ;
      ON    "R-W Asse Y Crimpatura".IMEF;
      O(    ;
      L     "R-W Asse Y Crimpatura".QAttualeAsseY;
      L     "Scambio dati OP".Q3AsseYCrimpatura;
      ==D   ;
      )     ;
      )     ;
      UN    "M65.4";
      UN    "M66.4";
      =     "M65.3";
NETWORK
TITLE =Asse Y Crimpatura Terzo Posizionamento Raggiunto

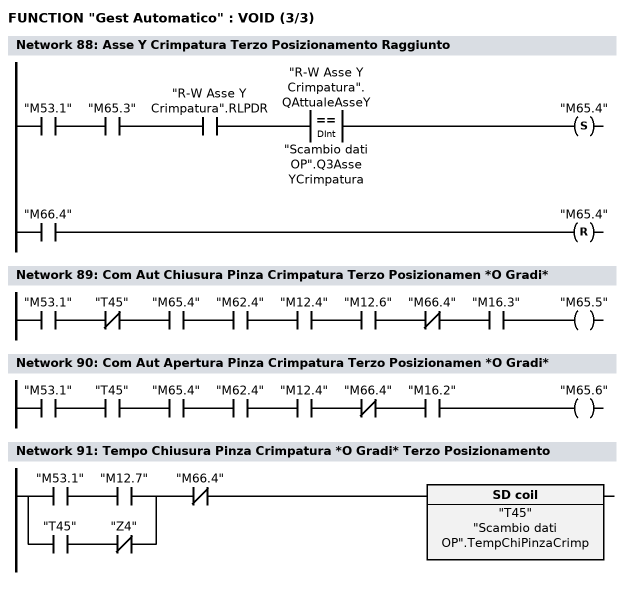
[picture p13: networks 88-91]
      U     "M53.1";
      U     "M65.3";
      U     "R-W Asse Y Crimpatura".RLPDR;
      U(    ;
      L     "R-W Asse Y Crimpatura".QAttualeAsseY;
      L     "Scambio dati OP".Q3AsseYCrimpatura;
      ==D   ;
      )     ;
      S     "M65.4";
      U     "M66.4";
      R     "M65.4";
      NOP   0;
NETWORK
TITLE =Com Aut Chiusura Pinza Crimpatura Terzo Posizionamen *O Gradi*

      U     "M53.1";
      UN    "T45";
      U     "M65.4";
      U     "M62.4";
      U     "M12.4";
      U     "M12.6";
      UN    "M66.4";
      U     "M16.3";
      =     "M65.5";
NETWORK
TITLE =Com Aut Apertura Pinza Crimpatura Terzo Posizionamen *O Gradi*

      U     "M53.1";
      U     "T45";
      U     "M65.4";
      U     "M62.4";
      U     "M12.4";
      UN    "M66.4";
      U     "M16.2";
      =     "M65.6";
NETWORK
TITLE =Tempo Chiusura Pinza Crimpatura *O Gradi* Terzo Posizionamento

      U(    ;
      U     "M53.1";
      U     "M12.7";
      O     ;
      U     "T45";
      UN    "Z4";
      )     ;
      UN    "M66.4";
      L     "Scambio dati OP".TempChiPinzaCrimp;
      SE    "T45";
      NOP   0;
      NOP   0;
      NOP   0;
      NOP   0;
NETWORK
TITLE =Numero di Crimpate da Eseguire *O Gradi* Terzo Posizionamento

      U     "EV103";
      U     "M65.5";
      U     "M12.4";
      U     "M62.4";
      UN    "M66.4";
      ZR    "Z4";
      BLD   101;
      U     "M65.2";
      L     "Scambio dati OP".NCrimp0Gradi;
      S     "Z4";
      U     "M66.4";
      R     "Z4";
      NOP   0;
      NOP   0;
      NOP   0;
NETWORK
TITLE =Com Aut Rotazione Polso a 45 Gradi Terzo Posizionamento

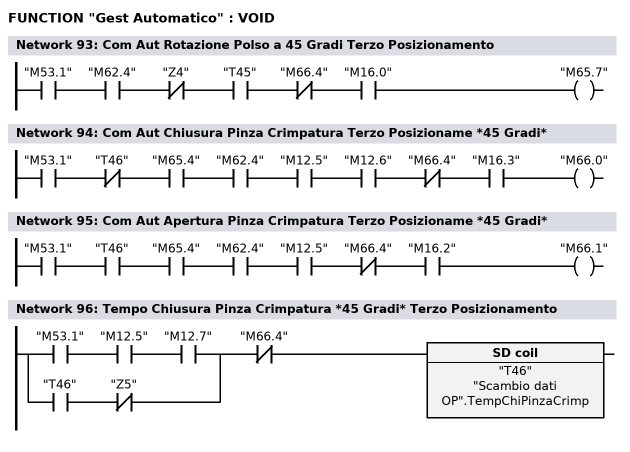
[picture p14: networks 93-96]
      U     "M53.1";
      U     "M62.4";
      UN    "Z4";
      U     "T45";
      UN    "M66.4";
      U     "M16.0";
      =     "M65.7";
NETWORK
TITLE =Com Aut Chiusura Pinza Crimpatura Terzo Posizioname *45 Gradi*

      U     "M53.1";
      UN    "T46";
      U     "M65.4";
      U     "M62.4";
      U     "M12.5";
      U     "M12.6";
      UN    "M66.4";
      U     "M16.3";
      =     "M66.0";
NETWORK
TITLE =Com Aut Apertura Pinza Crimpatura Terzo Posizioname *45 Gradi*

      U     "M53.1";
      U     "T46";
      U     "M65.4";
      U     "M62.4";
      U     "M12.5";
      UN    "M66.4";
      U     "M16.2";
      =     "M66.1";
NETWORK
TITLE =Tempo Chiusura Pinza Crimpatura *45 Gradi* Terzo Posizionamento

      U(    ;
      U     "M53.1";
      U     "M12.5";
      U     "M12.7";
      O     ;
      U     "T46";
      UN    "Z5";
      )     ;
      UN    "M66.4";
      L     "Scambio dati OP".TempChiPinzaCrimp;
      SE    "T46";
      NOP   0;
      NOP   0;
      NOP   0;
      NOP   0;
NETWORK
TITLE =Numero di Crimpate da Eseguire *45 Gradi* Terzo Posizionamento

      U     "EV103";
      U     "M66.0";
      U     "M12.5";
      U     "M62.4";
      UN    "M66.4";
      ZR    "Z5";
      BLD   101;
      U     "M65.2";
      L     "Scambio dati OP".NCrimp45Gradi;
      S     "Z5";
      U     "M66.4";
      R     "Z5";
      NOP   0;
      NOP   0;
      NOP   0;
NETWORK
TITLE =Com Aut Start Pos Base Asse Y Crimpatura dopo Terzo Crimpatura

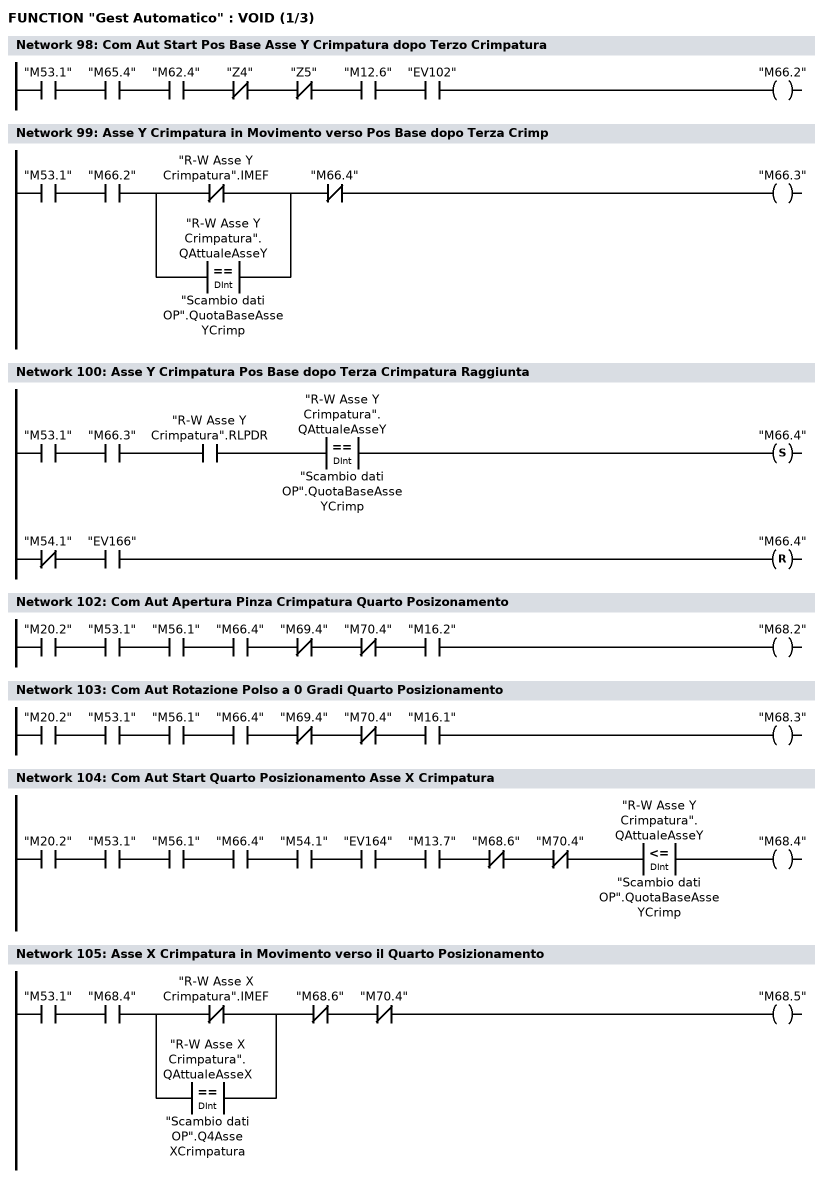
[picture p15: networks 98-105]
      U     "M53.1";
      U     "M65.4";
      U     "M62.4";
      UN    "Z4";
      UN    "Z5";
      U     "M12.6";
      U     "EV102";
      =     "M66.2";
NETWORK
TITLE =Asse Y Crimpatura in Movimento verso Pos Base dopo Terza Crimp

      U     "M53.1";
      U     "M66.2";
      U(    ;
      ON    "R-W Asse Y Crimpatura".IMEF;
      O(    ;
      L     "R-W Asse Y Crimpatura".QAttualeAsseY;
      L     "Scambio dati OP".QuotaBaseAsseYCrimp;
      ==D   ;
      )     ;
      )     ;
      UN    "M66.4";
      =     "M66.3";
NETWORK
TITLE =Asse Y Crimpatura Pos Base dopo Terza Crimpatura Raggiunta

      U     "M53.1";
      U     "M66.3";
      U     "R-W Asse Y Crimpatura".RLPDR;
      U(    ;
      L     "R-W Asse Y Crimpatura".QAttualeAsseY;
      L     "Scambio dati OP".QuotaBaseAsseYCrimp;
      ==D   ;
      )     ;
      S     "M66.4";
      UN    "M54.1";
      U     "EV166";
      R     "M66.4";
      NOP   0;
NETWORK
TITLE ======== Quarto Posizionamento Crimpatura =======

NETWORK
TITLE =Com Aut Apertura Pinza Crimpatura Quarto Posizonamento

      U     "M20.2";
      U     "M53.1";
      U     "M56.1";
      U     "M66.4";
      UN    "M69.4";
      UN    "M70.4";
      U     "M16.2";
      =     "M68.2";
NETWORK
TITLE =Com Aut Rotazione Polso a 0 Gradi Quarto Posizionamento

      U     "M20.2";
      U     "M53.1";
      U     "M56.1";
      U     "M66.4";
      UN    "M69.4";
      UN    "M70.4";
      U     "M16.1";
      =     "M68.3";
NETWORK
TITLE =Com Aut Start Quarto Posizionamento Asse X Crimpatura

      U     "M20.2";
      U     "M53.1";
      U     "M56.1";
      U     "M66.4";
      U     "M54.1";
      U     "EV164";
      U     "M13.7";
      UN    "M68.6";
      UN    "M70.4";
      U(    ;
      L     "R-W Asse Y Crimpatura".QAttualeAsseY;
      L     "Scambio dati OP".QuotaBaseAsseYCrimp;
      <=D   ;
      )     ;
      =     "M68.4";
NETWORK
TITLE =Asse X Crimpatura in Movimento verso il Quarto Posizionamento

      U     "M53.1";
      U     "M68.4";
      U(    ;
      ON    "R-W Asse X Crimpatura".IMEF;
      O(    ;
      L     "R-W Asse X Crimpatura".QAttualeAsseX;
      L     "Scambio dati OP".Q4AsseXCrimpatura;
      ==D   ;
      )     ;
      )     ;
      UN    "M68.6";
      UN    "M70.4";
      =     "M68.5";
NETWORK
TITLE =Asse X Crimpatura Quarto Posizionamento Raggiunto

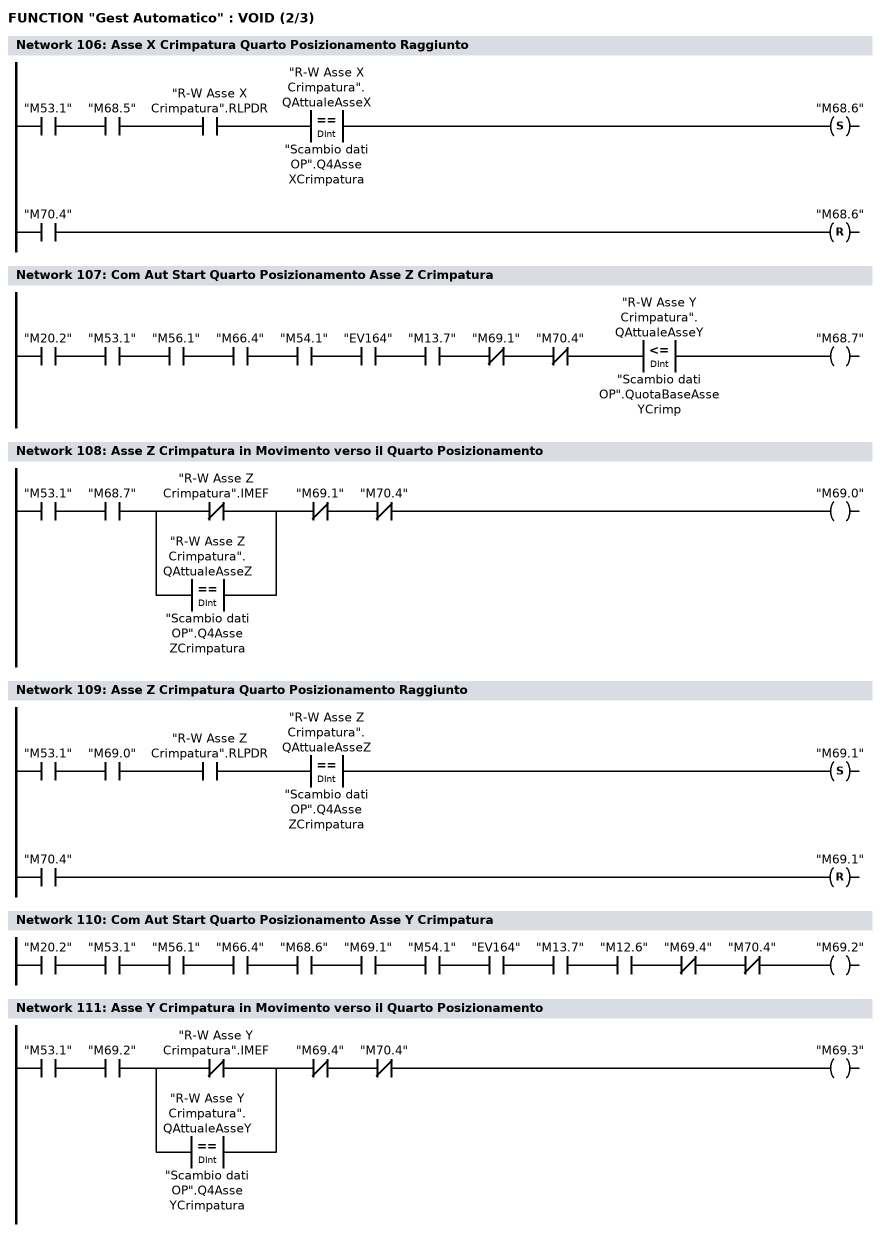
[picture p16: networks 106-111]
      U     "M53.1";
      U     "M68.5";
      U     "R-W Asse X Crimpatura".RLPDR;
      U(    ;
      L     "R-W Asse X Crimpatura".QAttualeAsseX;
      L     "Scambio dati OP".Q4AsseXCrimpatura;
      ==D   ;
      )     ;
      S     "M68.6";
      U     "M70.4";
      R     "M68.6";
      NOP   0;
NETWORK
TITLE =Com Aut Start Quarto Posizionamento Asse Z Crimpatura

      U     "M20.2";
      U     "M53.1";
      U     "M56.1";
      U     "M66.4";
      U     "M54.1";
      U     "EV164";
      U     "M13.7";
      UN    "M69.1";
      UN    "M70.4";
      U(    ;
      L     "R-W Asse Y Crimpatura".QAttualeAsseY;
      L     "Scambio dati OP".QuotaBaseAsseYCrimp;
      <=D   ;
      )     ;
      =     "M68.7";
NETWORK
TITLE =Asse Z Crimpatura in Movimento verso il Quarto Posizionamento

      U     "M53.1";
      U     "M68.7";
      U(    ;
      ON    "R-W Asse Z Crimpatura".IMEF;
      O(    ;
      L     "R-W Asse Z Crimpatura".QAttualeAsseZ;
      L     "Scambio dati OP".Q4AsseZCrimpatura;
      ==D   ;
      )     ;
      )     ;
      UN    "M69.1";
      UN    "M70.4";
      =     "M69.0";
NETWORK
TITLE =Asse Z Crimpatura Quarto Posizionamento Raggiunto

      U     "M53.1";
      U     "M69.0";
      U     "R-W Asse Z Crimpatura".RLPDR;
      U(    ;
      L     "R-W Asse Z Crimpatura".QAttualeAsseZ;
      L     "Scambio dati OP".Q4AsseZCrimpatura;
      ==D   ;
      )     ;
      S     "M69.1";
      U     "M70.4";
      R     "M69.1";
      NOP   0;
NETWORK
TITLE =Com Aut Start Quarto Posizionamento Asse Y Crimpatura

      U     "M20.2";
      U     "M53.1";
      U     "M56.1";
      U     "M66.4";
      U     "M68.6";
      U     "M69.1";
      U     "M54.1";
      U     "EV164";
      U     "M13.7";
      U     "M12.6";
      UN    "M69.4";
      UN    "M70.4";
      =     "M69.2";
NETWORK
TITLE =Asse Y Crimpatura in Movimento verso il Quarto Posizionamento

      U     "M53.1";
      U     "M69.2";
      U(    ;
      ON    "R-W Asse Y Crimpatura".IMEF;
      O(    ;
      L     "R-W Asse Y Crimpatura".QAttualeAsseY;
      L     "Scambio dati OP".Q4AsseYCrimpatura;
      ==D   ;
      )     ;
      )     ;
      UN    "M69.4";
      UN    "M70.4";
      =     "M69.3";
NETWORK
TITLE =Asse Y Crimpatura Quarto Posizionamento Raggiunto

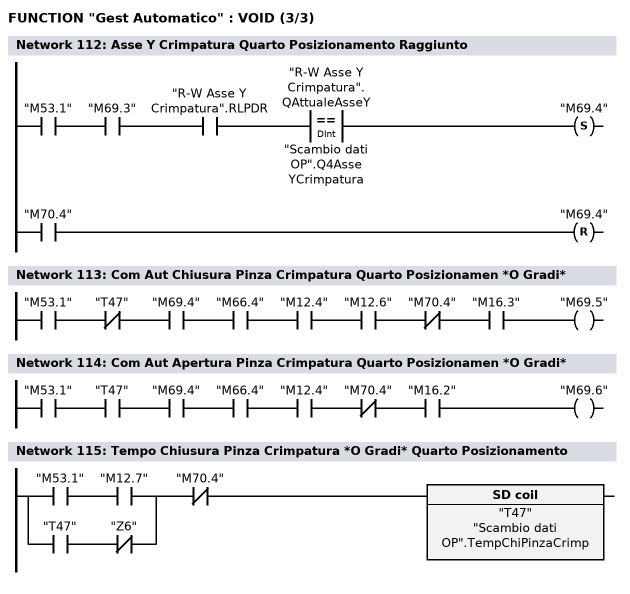
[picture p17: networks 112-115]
      U     "M53.1";
      U     "M69.3";
      U     "R-W Asse Y Crimpatura".RLPDR;
      U(    ;
      L     "R-W Asse Y Crimpatura".QAttualeAsseY;
      L     "Scambio dati OP".Q4AsseYCrimpatura;
      ==D   ;
      )     ;
      S     "M69.4";
      U     "M70.4";
      R     "M69.4";
      NOP   0;
NETWORK
TITLE =Com Aut Chiusura Pinza Crimpatura Quarto Posizionamen *O Gradi*

      U     "M53.1";
      UN    "T47";
      U     "M69.4";
      U     "M66.4";
      U     "M12.4";
      U     "M12.6";
      UN    "M70.4";
      U     "M16.3";
      =     "M69.5";
NETWORK
TITLE =Com Aut Apertura Pinza Crimpatura Quarto Posizionamen *O Gradi*

      U     "M53.1";
      U     "T47";
      U     "M69.4";
      U     "M66.4";
      U     "M12.4";
      UN    "M70.4";
      U     "M16.2";
      =     "M69.6";
NETWORK
TITLE =Tempo Chiusura Pinza Crimpatura *O Gradi* Quarto Posizionamento

      U(    ;
      U     "M53.1";
      U     "M12.7";
      O     ;
      U     "T47";
      UN    "Z6";
      )     ;
      UN    "M70.4";
      L     "Scambio dati OP".TempChiPinzaCrimp;
      SE    "T47";
      NOP   0;
      NOP   0;
      NOP   0;
      NOP   0;
NETWORK
TITLE =Numero di Crimpate da Eseguire *O Gradi* Quarto Posizionamento

      U     "EV103";
      U     "M69.5";
      U     "M12.4";
      U     "M66.4";
      UN    "M70.4";
      ZR    "Z6";
      BLD   101;
      U     "M69.2";
      L     "Scambio dati OP".NCrimp0Gradi;
      S     "Z6";
      U     "M70.4";
      R     "Z6";
      NOP   0;
      NOP   0;
      NOP   0;
NETWORK
TITLE =Com Aut Rotazione Polso a 45 Gradi Quarto Posizionamento

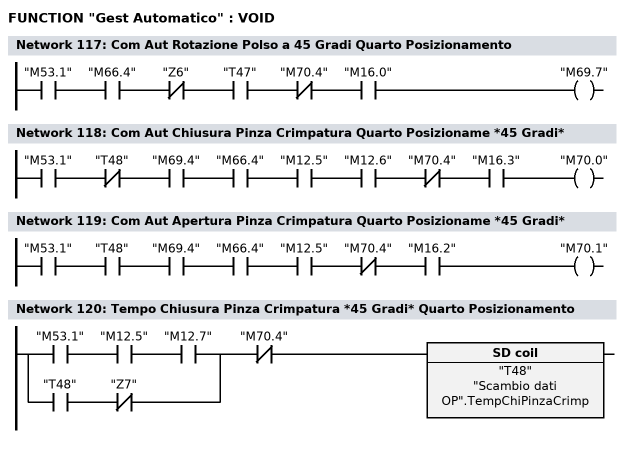
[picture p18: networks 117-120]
      U     "M53.1";
      U     "M66.4";
      UN    "Z6";
      U     "T47";
      UN    "M70.4";
      U     "M16.0";
      =     "M69.7";
NETWORK
TITLE =Com Aut Chiusura Pinza Crimpatura Quarto Posizioname *45 Gradi*

      U     "M53.1";
      UN    "T48";
      U     "M69.4";
      U     "M66.4";
      U     "M12.5";
      U     "M12.6";
      UN    "M70.4";
      U     "M16.3";
      =     "M70.0";
NETWORK
TITLE =Com Aut Apertura Pinza Crimpatura Quarto Posizioname *45 Gradi*

      U     "M53.1";
      U     "T48";
      U     "M69.4";
      U     "M66.4";
      U     "M12.5";
      UN    "M70.4";
      U     "M16.2";
      =     "M70.1";
NETWORK
TITLE =Tempo Chiusura Pinza Crimpatura *45 Gradi* Quarto Posizionamento

      U(    ;
      U     "M53.1";
      U     "M12.5";
      U     "M12.7";
      O     ;
      U     "T48";
      UN    "Z7";
      )     ;
      UN    "M70.4";
      L     "Scambio dati OP".TempChiPinzaCrimp;
      SE    "T48";
      NOP   0;
      NOP   0;
      NOP   0;
      NOP   0;
NETWORK
TITLE =Numero di Crimpate da Eseguire *45 Gradi* Quarto Posizionamento

      U     "EV103";
      U     "M70.0";
      U     "M12.5";
      U     "M66.4";
      UN    "M70.4";
      ZR    "Z7";
      BLD   101;
      U     "M69.2";
      L     "Scambio dati OP".NCrimp45Gradi;
      S     "Z7";
      U     "M70.4";
      R     "Z7";
      NOP   0;
      NOP   0;
      NOP   0;
NETWORK
TITLE =Com Aut Start Pos Base Asse Y Crimpatura dopo Quarto Crimpatura

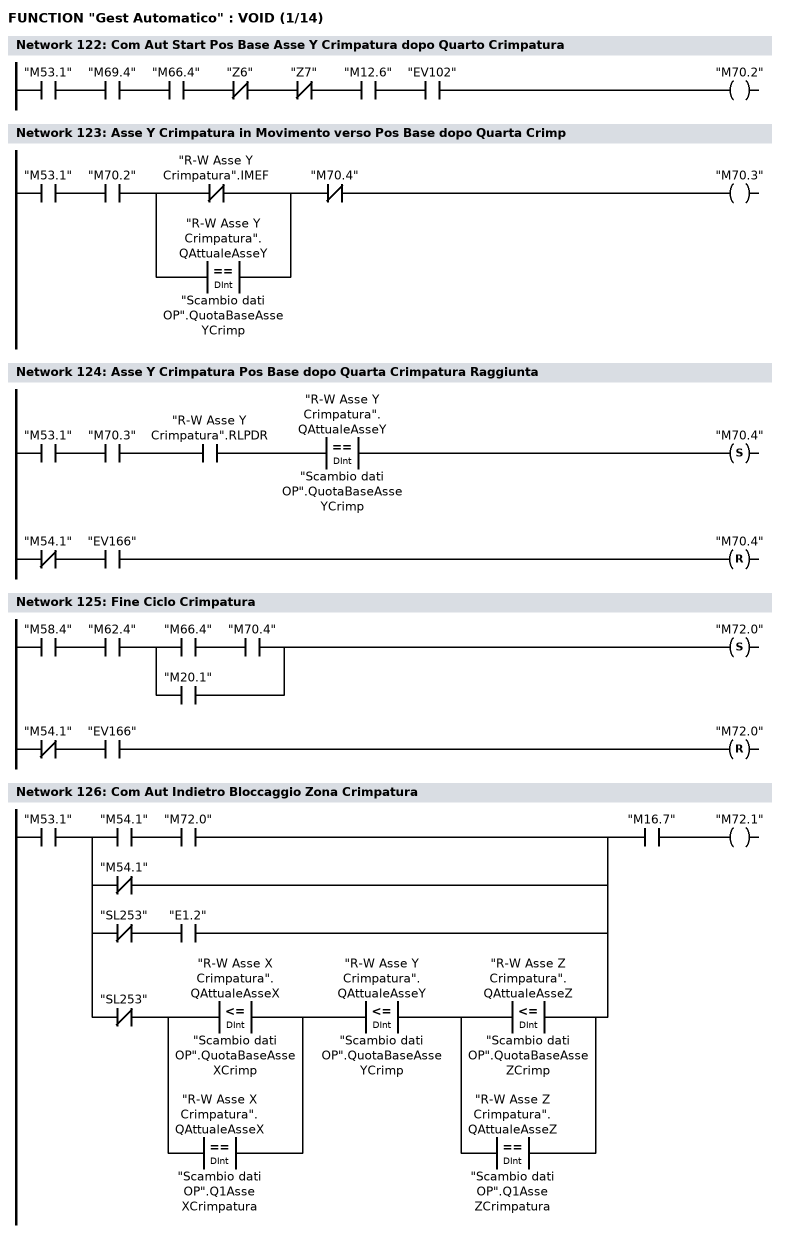
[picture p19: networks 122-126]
      U     "M53.1";
      U     "M69.4";
      U     "M66.4";
      UN    "Z6";
      UN    "Z7";
      U     "M12.6";
      U     "EV102";
      =     "M70.2";
NETWORK
TITLE =Asse Y Crimpatura in Movimento verso Pos Base dopo Quarta Crimp

      U     "M53.1";
      U     "M70.2";
      U(    ;
      ON    "R-W Asse Y Crimpatura".IMEF;
      O(    ;
      L     "R-W Asse Y Crimpatura".QAttualeAsseY;
      L     "Scambio dati OP".QuotaBaseAsseYCrimp;
      ==D   ;
      )     ;
      )     ;
      UN    "M70.4";
      =     "M70.3";
NETWORK
TITLE =Asse Y Crimpatura Pos Base dopo Quarta Crimpatura Raggiunta

      U     "M53.1";
      U     "M70.3";
      U     "R-W Asse Y Crimpatura".RLPDR;
      U(    ;
      L     "R-W Asse Y Crimpatura".QAttualeAsseY;
      L     "Scambio dati OP".QuotaBaseAsseYCrimp;
      ==D   ;
      )     ;
      S     "M70.4";
      UN    "M54.1";
      U     "EV166";
      R     "M70.4";
      NOP   0;
NETWORK
TITLE =Fine Ciclo Crimpatura

      U     "M58.4";
      U     "M62.4";
      U(    ;
      U     "M66.4";
      U     "M70.4";
      O     "M20.1";
      )     ;
      S     "M72.0";
      UN    "M54.1";
      U     "EV166";
      R     "M72.0";
      NOP   0;
NETWORK
TITLE =Com Aut Indietro Bloccaggio Zona Crimpatura

      U     "M53.1";
      U(    ;
      U     "M54.1";
      U     "M72.0";
      ON    "M54.1";
      O     ;
      UN    "SL253";
      U     "E1.2";
      O     ;
      UN    "SL253";
      U(    ;
      O(    ;
      L     "R-W Asse X Crimpatura".QAttualeAsseX;
      L     "Scambio dati OP".QuotaBaseAsseXCrimp;
      <=D   ;
      )     ;
      O(    ;
      L     "R-W Asse X Crimpatura".QAttualeAsseX;
      L     "Scambio dati OP".Q1AsseXCrimpatura;
      ==D   ;
      )     ;
      )     ;
      U(    ;
      L     "R-W Asse Y Crimpatura".QAttualeAsseY;
      L     "Scambio dati OP".QuotaBaseAsseYCrimp;
      <=D   ;
      )     ;
      U(    ;
      O(    ;
      L     "R-W Asse Z Crimpatura".QAttualeAsseZ;
      L     "Scambio dati OP".QuotaBaseAsseZCrimp;
      <=D   ;
      )     ;
      O(    ;
      L     "R-W Asse Z Crimpatura".QAttualeAsseZ;
      L     "Scambio dati OP".Q1AsseZCrimpatura;
      ==D   ;
      )     ;
      )     ;
      )     ;
      U     "M16.7";
      =     "M72.1";
NETWORK
TITLE =Com Aut Indietro Fermo Zona Crimpatura

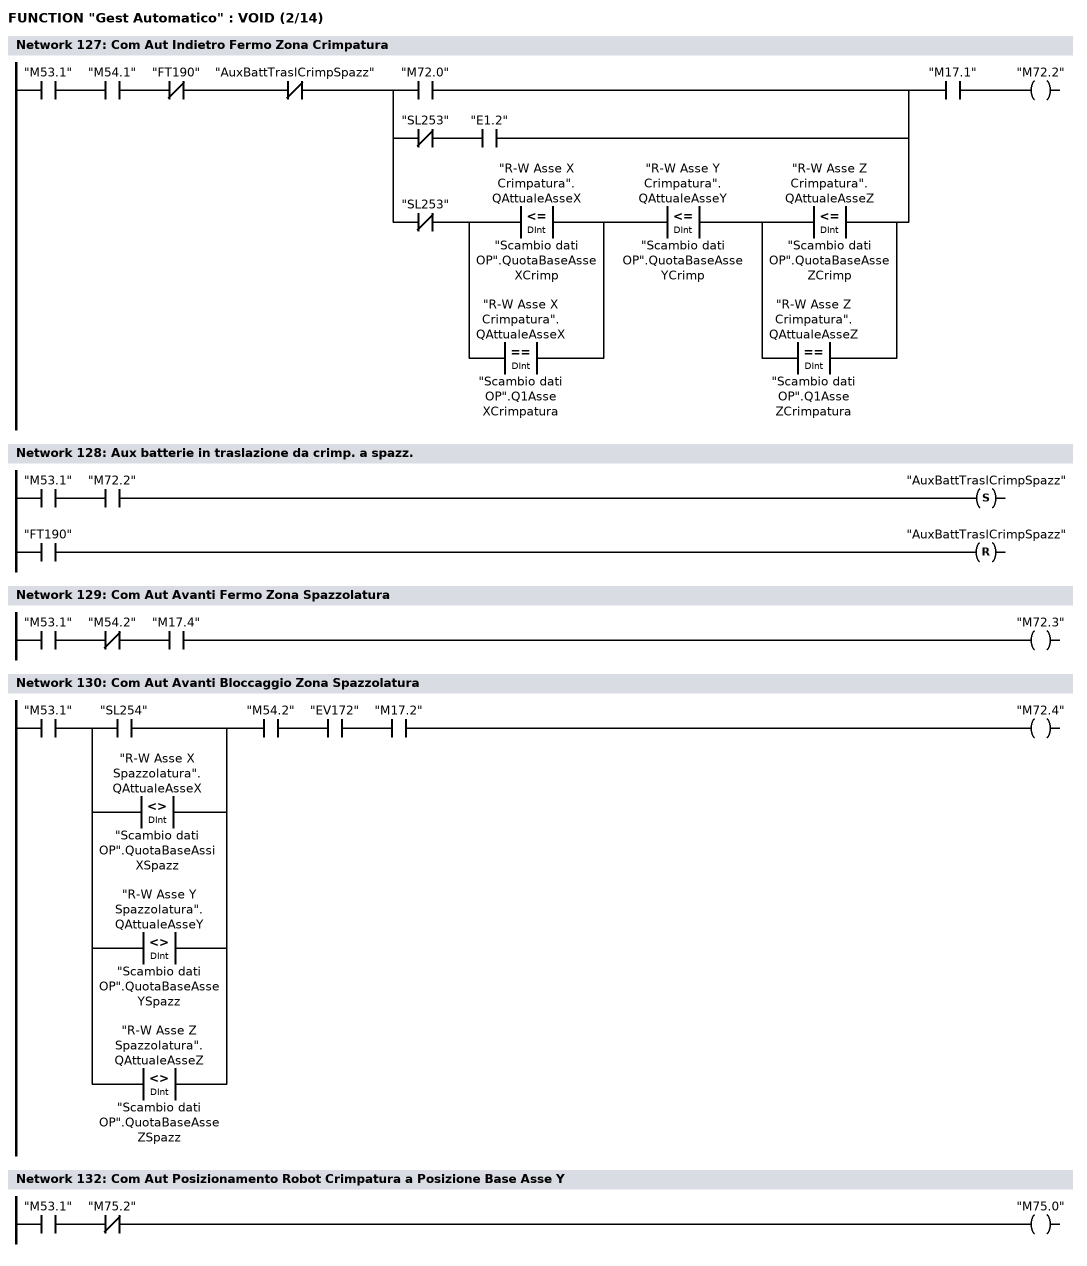
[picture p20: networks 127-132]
      U     "M53.1";
      U     "M54.1";
      UN    "FT190";
      UN    "AuxBattTraslCrimpSpazz";
      U(    ;
      O     "M72.0";
      O     ;
      UN    "SL253";
      U     "E1.2";
      O     ;
      UN    "SL253";
      U(    ;
      O(    ;
      L     "R-W Asse X Crimpatura".QAttualeAsseX;
      L     "Scambio dati OP".QuotaBaseAsseXCrimp;
      <=D   ;
      )     ;
      O(    ;
      L     "R-W Asse X Crimpatura".QAttualeAsseX;
      L     "Scambio dati OP".Q1AsseXCrimpatura;
      ==D   ;
      )     ;
      )     ;
      U(    ;
      L     "R-W Asse Y Crimpatura".QAttualeAsseY;
      L     "Scambio dati OP".QuotaBaseAsseYCrimp;
      <=D   ;
      )     ;
      U(    ;
      O(    ;
      L     "R-W Asse Z Crimpatura".QAttualeAsseZ;
      L     "Scambio dati OP".QuotaBaseAsseZCrimp;
      <=D   ;
      )     ;
      O(    ;
      L     "R-W Asse Z Crimpatura".QAttualeAsseZ;
      L     "Scambio dati OP".Q1AsseZCrimpatura;
      ==D   ;
      )     ;
      )     ;
      )     ;
      U     "M17.1";
      =     "M72.2";
NETWORK
TITLE =Aux batterie in traslazione da crimp. a spazz.

      U     "M53.1";
      U     "M72.2";
      S     "AuxBattTraslCrimpSpazz";
      U     "FT190";
      R     "AuxBattTraslCrimpSpazz";
      NOP   0;
NETWORK
TITLE =Com Aut Avanti Fermo Zona Spazzolatura

      U     "M53.1";
      UN    "M54.2";
      U     "M17.4";
      =     "M72.3";
NETWORK
TITLE =Com Aut Avanti Bloccaggio Zona Spazzolatura

      U     "M53.1";
      U(    ;
      O     "SL254";
      O(    ;
      L     "R-W Asse X Spazzolatura".QAttualeAsseX;
      L     "Scambio dati OP".QuotaBaseAssiXSpazz;
      <>D   ;
      )     ;
      O(    ;
      L     "R-W Asse Y Spazzolatura".QAttualeAsseY;
      L     "Scambio dati OP".QuotaBaseAsseYSpazz;
      <>D   ;
      )     ;
      O(    ;
      L     "R-W Asse Z Spazzolatura".QAttualeAsseZ;
      L     "Scambio dati OP".QuotaBaseAsseZSpazz;
      <>D   ;
      )     ;
      )     ;
      U     "M54.2";
      U     "EV172";
      U     "M17.2";
      =     "M72.4";
NETWORK
TITLE ======== Ciclo Automatico Spazzolatura ========

NETWORK
TITLE =Com Aut Posizionamento Robot Crimpatura a Posizione Base Asse Y

      U     "M53.1";
      UN    "M75.2";
      =     "M75.0";
NETWORK
TITLE =Asse Y Spazzolatura in Movimento verso Posizione Base

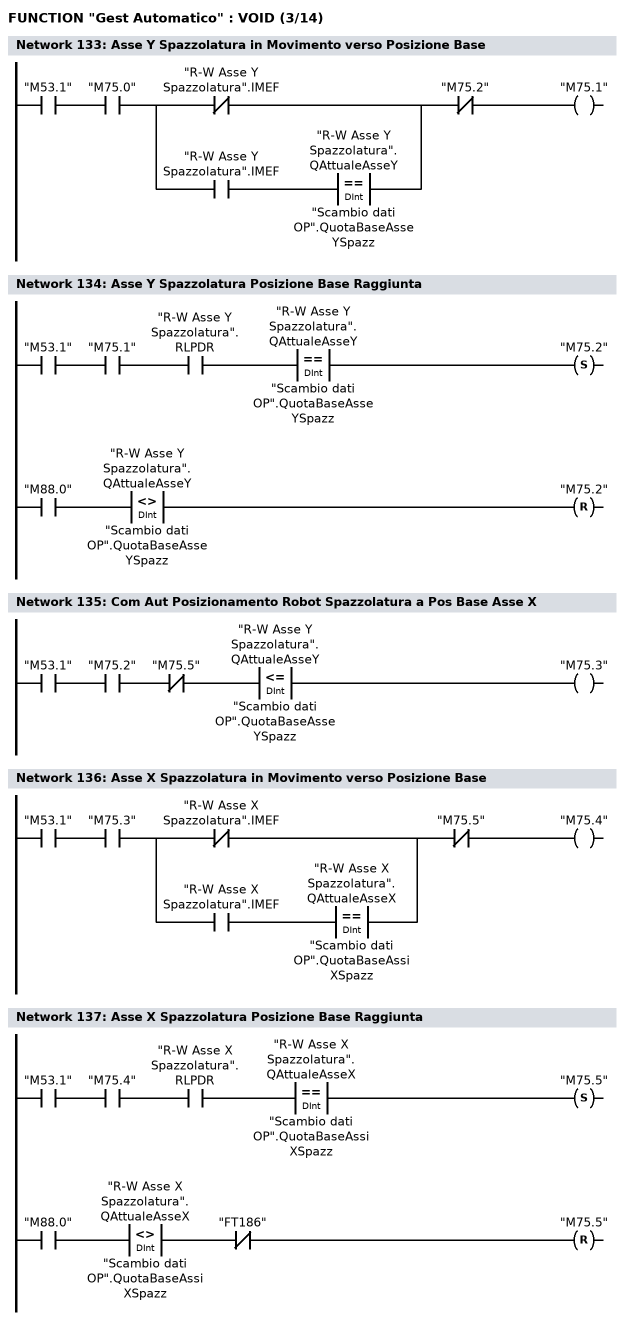
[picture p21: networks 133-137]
      U     "M53.1";
      U     "M75.0";
      U(    ;
      ON    "R-W Asse Y Spazzolatura".IMEF;
      O     ;
      U     "R-W Asse Y Spazzolatura".IMEF;
      U(    ;
      L     "R-W Asse Y Spazzolatura".QAttualeAsseY;
      L     "Scambio dati OP".QuotaBaseAsseYSpazz;
      ==D   ;
      )     ;
      )     ;
      UN    "M75.2";
      =     "M75.1";
NETWORK
TITLE =Asse Y Spazzolatura Posizione Base Raggiunta

      U     "M53.1";
      U     "M75.1";
      U     "R-W Asse Y Spazzolatura".RLPDR;
      U(    ;
      L     "R-W Asse Y Spazzolatura".QAttualeAsseY;
      L     "Scambio dati OP".QuotaBaseAsseYSpazz;
      ==D   ;
      )     ;
      S     "M75.2";
      U     "M88.0";
      U(    ;
      L     "R-W Asse Y Spazzolatura".QAttualeAsseY;
      L     "Scambio dati OP".QuotaBaseAsseYSpazz;
      <>D   ;
      )     ;
      R     "M75.2";
      NOP   0;
NETWORK
TITLE =Com Aut Posizionamento Robot Spazzolatura a Pos Base Asse X

      U     "M53.1";
      U     "M75.2";
      UN    "M75.5";
      U(    ;
      L     "R-W Asse Y Spazzolatura".QAttualeAsseY;
      L     "Scambio dati OP".QuotaBaseAsseYSpazz;
      <=D   ;
      )     ;
      =     "M75.3";
NETWORK
TITLE =Asse X Spazzolatura in Movimento verso Posizione Base

      U     "M53.1";
      U     "M75.3";
      U(    ;
      ON    "R-W Asse X Spazzolatura".IMEF;
      O     ;
      U     "R-W Asse X Spazzolatura".IMEF;
      U(    ;
      L     "R-W Asse X Spazzolatura".QAttualeAsseX;
      L     "Scambio dati OP".QuotaBaseAssiXSpazz;
      ==D   ;
      )     ;
      )     ;
      UN    "M75.5";
      =     "M75.4";
NETWORK
TITLE =Asse X Spazzolatura Posizione Base Raggiunta

      U     "M53.1";
      U     "M75.4";
      U     "R-W Asse X Spazzolatura".RLPDR;
      U(    ;
      L     "R-W Asse X Spazzolatura".QAttualeAsseX;
      L     "Scambio dati OP".QuotaBaseAssiXSpazz;
      ==D   ;
      )     ;
      S     "M75.5";
      U     "M88.0";
      U(    ;
      L     "R-W Asse X Spazzolatura".QAttualeAsseX;
      L     "Scambio dati OP".QuotaBaseAssiXSpazz;
      <>D   ;
      )     ;
      UN    "FT186";
      R     "M75.5";
      NOP   0;
NETWORK
TITLE =Com Aut Posizionamento Robot Spazzolatura a Pos Base Asse Z

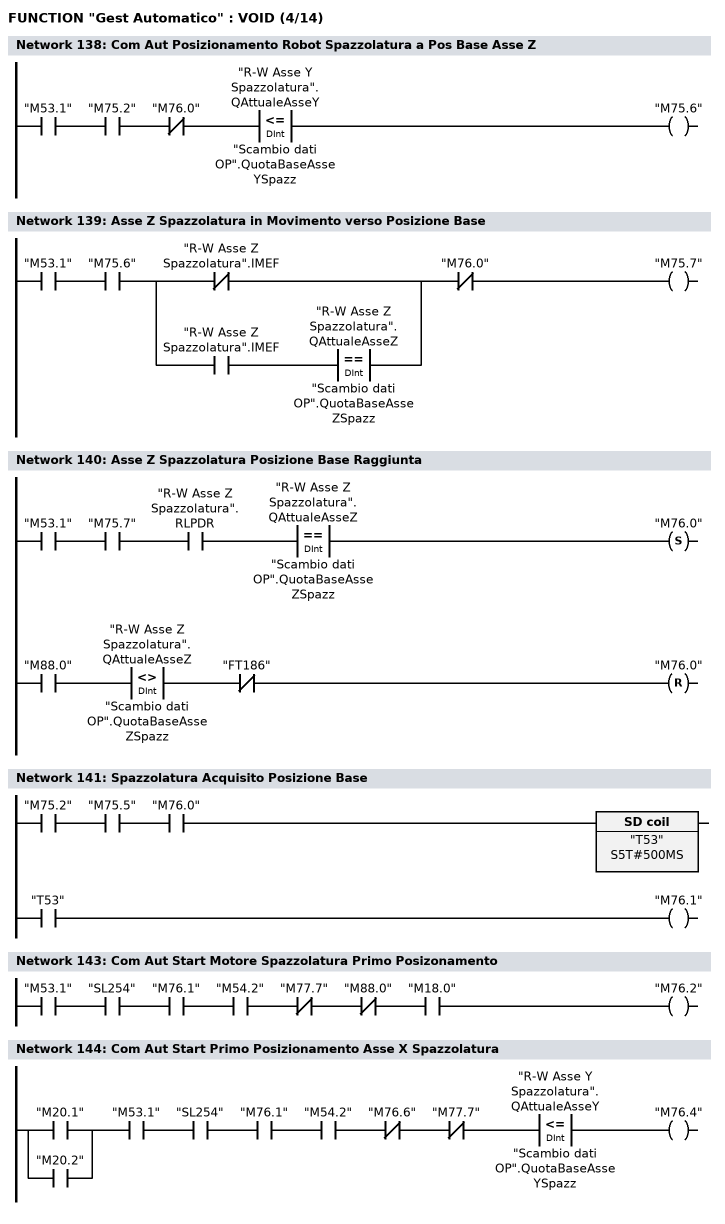
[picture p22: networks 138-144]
      U     "M53.1";
      U     "M75.2";
      UN    "M76.0";
      U(    ;
      L     "R-W Asse Y Spazzolatura".QAttualeAsseY;
      L     "Scambio dati OP".QuotaBaseAsseYSpazz;
      <=D   ;
      )     ;
      =     "M75.6";
NETWORK
TITLE =Asse Z Spazzolatura in Movimento verso Posizione Base

      U     "M53.1";
      U     "M75.6";
      U(    ;
      ON    "R-W Asse Z Spazzolatura".IMEF;
      O     ;
      U     "R-W Asse Z Spazzolatura".IMEF;
      U(    ;
      L     "R-W Asse Z Spazzolatura".QAttualeAsseZ;
      L     "Scambio dati OP".QuotaBaseAsseZSpazz;
      ==D   ;
      )     ;
      )     ;
      UN    "M76.0";
      =     "M75.7";
NETWORK
TITLE =Asse Z Spazzolatura Posizione Base Raggiunta

      U     "M53.1";
      U     "M75.7";
      U     "R-W Asse Z Spazzolatura".RLPDR;
      U(    ;
      L     "R-W Asse Z Spazzolatura".QAttualeAsseZ;
      L     "Scambio dati OP".QuotaBaseAsseZSpazz;
      ==D   ;
      )     ;
      S     "M76.0";
      U     "M88.0";
      U(    ;
      L     "R-W Asse Z Spazzolatura".QAttualeAsseZ;
      L     "Scambio dati OP".QuotaBaseAsseZSpazz;
      <>D   ;
      )     ;
      UN    "FT186";
      R     "M76.0";
      NOP   0;
NETWORK
TITLE =Spazzolatura Acquisito Posizione Base

      U     "M75.2";
      U     "M75.5";
      U     "M76.0";
      L     S5T#500MS;
      SE    "T53";
      NOP   0;
      NOP   0;
      NOP   0;
      U     "T53";
      =     "M76.1";
NETWORK
TITLE ======== Primo Posizionamento Spazzolatura =======

NETWORK
TITLE =Com Aut Start Motore Spazzolatura Primo Posizonamento

      U     "M53.1";
      U     "SL254";
      U     "M76.1";
      U     "M54.2";
      UN    "M77.7";
      UN    "M88.0";
      U     "M18.0";
      =     "M76.2";
NETWORK
TITLE =Com Aut Start Primo Posizionamento Asse X Spazzolatura

      U(    ;
      O     "M20.1";
      O     "M20.2";
      )     ;
      U     "M53.1";
      U     "SL254";
      U     "M76.1";
      U     "M54.2";
      UN    "M76.6";
      UN    "M77.7";
      U(    ;
      L     "R-W Asse Y Spazzolatura".QAttualeAsseY;
      L     "Scambio dati OP".QuotaBaseAsseYSpazz;
      <=D   ;
      )     ;
      =     "M76.4";
NETWORK
TITLE =Asse X Spazzolatura in Movimento verso il Primo Posizionamento

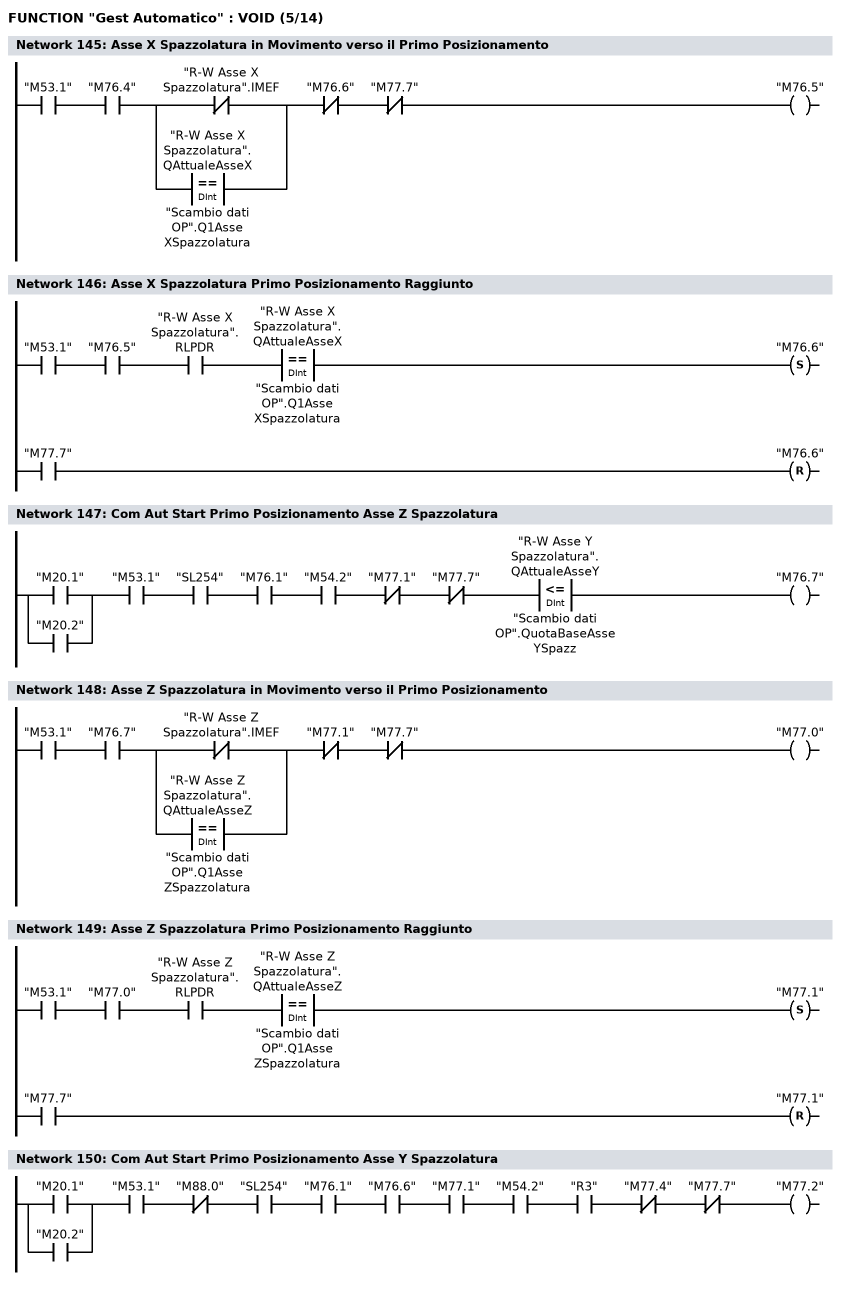
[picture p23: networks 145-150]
      U     "M53.1";
      U     "M76.4";
      U(    ;
      ON    "R-W Asse X Spazzolatura".IMEF;
      O(    ;
      L     "R-W Asse X Spazzolatura".QAttualeAsseX;
      L     "Scambio dati OP".Q1AsseXSpazzolatura;
      ==D   ;
      )     ;
      )     ;
      UN    "M76.6";
      UN    "M77.7";
      =     "M76.5";
NETWORK
TITLE =Asse X Spazzolatura Primo Posizionamento Raggiunto

      U     "M53.1";
      U     "M76.5";
      U     "R-W Asse X Spazzolatura".RLPDR;
      U(    ;
      L     "R-W Asse X Spazzolatura".QAttualeAsseX;
      L     "Scambio dati OP".Q1AsseXSpazzolatura;
      ==D   ;
      )     ;
      S     "M76.6";
      U     "M77.7";
      R     "M76.6";
      NOP   0;
NETWORK
TITLE =Com Aut Start Primo Posizionamento Asse Z Spazzolatura

      U(    ;
      O     "M20.1";
      O     "M20.2";
      )     ;
      U     "M53.1";
      U     "SL254";
      U     "M76.1";
      U     "M54.2";
      UN    "M77.1";
      UN    "M77.7";
      U(    ;
      L     "R-W Asse Y Spazzolatura".QAttualeAsseY;
      L     "Scambio dati OP".QuotaBaseAsseYSpazz;
      <=D   ;
      )     ;
      =     "M76.7";
NETWORK
TITLE =Asse Z Spazzolatura in Movimento verso il Primo Posizionamento

      U     "M53.1";
      U     "M76.7";
      U(    ;
      ON    "R-W Asse Z Spazzolatura".IMEF;
      O(    ;
      L     "R-W Asse Z Spazzolatura".QAttualeAsseZ;
      L     "Scambio dati OP".Q1AsseZSpazzolatura;
      ==D   ;
      )     ;
      )     ;
      UN    "M77.1";
      UN    "M77.7";
      =     "M77.0";
NETWORK
TITLE =Asse Z Spazzolatura Primo Posizionamento Raggiunto

      U     "M53.1";
      U     "M77.0";
      U     "R-W Asse Z Spazzolatura".RLPDR;
      U(    ;
      L     "R-W Asse Z Spazzolatura".QAttualeAsseZ;
      L     "Scambio dati OP".Q1AsseZSpazzolatura;
      ==D   ;
      )     ;
      S     "M77.1";
      U     "M77.7";
      R     "M77.1";
      NOP   0;
NETWORK
TITLE =Com Aut Start Primo Posizionamento Asse Y Spazzolatura

      U(    ;
      O     "M20.1";
      O     "M20.2";
      )     ;
      U     "M53.1";
      UN    "M88.0";
      U     "SL254";
      U     "M76.1";
      U     "M76.6";
      U     "M77.1";
      U     "M54.2";
      U     "R3";
      UN    "M77.4";
      UN    "M77.7";
      =     "M77.2";
NETWORK
TITLE =Asse Y Spazzolatura in Movimento verso il Primo Posizionamento

      U     "M53.1";
      U     "M77.2";
      U(    ;
      ON    "R-W Asse Y Spazzolatura".IMEF;
      O(    ;
      L     "R-W Asse Y Spazzolatura".QAttualeAsseY;
      L     "Scambio dati OP".Q1AsseYSpazzolatura;
      ==D   ;
      )     ;
      )     ;
      UN    "M77.4";
      UN    "M77.7";
      =     "M77.3";
NETWORK
TITLE =Asse Y Spazzolatura Primo Posizionamento Raggiunto

      U     "M53.1";
      U     "M77.3";
      U     "R-W Asse Y Spazzolatura".RLPDR;
      U(    ;
      L     "R-W Asse Y Spazzolatura".QAttualeAsseY;
      L     "Scambio dati OP".Q1AsseYSpazzolatura;
      ==D   ;
      )     ;
      S     "M77.4";
      U     "M77.7";
      R     "M77.4";
      NOP   0;
NETWORK
TITLE =Tempo di Spazzolatura Primo Posizionamento

      U     "M53.1";
      U     "M77.4";
      L     "Scambio dati OP".TempChiPinzaCrimp;
      SE    "T49";
      NOP   0;
      NOP   0;
      NOP   0;
      NOP   0;
NETWORK
TITLE =Com Aut Start Pos Base Asse Y Spazzolatura dopo Prima Spazzolata

      U     "M53.1";
      U     "M77.4";
      U     "T49";
      UN    "M77.7";
      =     "M77.5";
NETWORK
TITLE =Asse Y Spazzolatura in Movimento verso Pos Base dopo Prima Spazz

      U     "M53.1";
      U     "M77.5";
      U(    ;
      ON    "R-W Asse Y Spazzolatura".IMEF;
      O(    ;
      L     "R-W Asse Y Spazzolatura".QAttualeAsseY;
      L     "Scambio dati OP".QuotaBaseAsseYSpazz;
      ==D   ;
      )     ;
      )     ;
      UN    "M77.7";
      =     "M77.6";
NETWORK
TITLE =Asse Y Spazzolatura Posizione Base dopo Prima Spazzol. Raggiunta

      U     "M53.1";
      U     "M77.6";
      U     "R-W Asse Y Spazzolatura".RLPDR;
      U(    ;
      L     "R-W Asse Y Spazzolatura".QAttualeAsseY;
      L     "Scambio dati OP".QuotaBaseAsseYSpazz;
      ==D   ;
      )     ;
      S     "M77.7";
      U(    ;
      UN    "M54.2";
      U     "EV172";
      O     ;
      U     "M88.0";
      U(    ;
      L     "R-W Asse Z Spazzolatura".QAttualeAsseZ;
      L     "Scambio dati OP".QuotaBaseAsseZSpazz;
      <>D   ;
      )     ;
      U     "M54.1";
      )     ;
      R     "M77.7";
      NOP   0;
NETWORK
TITLE ======== Secondo Posizionamento Spazzolatura =======

NETWORK
TITLE =Com Aut Start Motore Spazzolatura Secondo Posizonamento

      U     "M53.1";
      U     "M76.1";
      U     "M77.7";
      U     "M54.2";
      UN    "M80.7";
      U     "M18.0";
      =     "M79.2";
NETWORK
TITLE =Com Aut Start Secondo Posizionamento Asse X Spazzolatura

      U(    ;
      O     "M20.1";
      O     "M20.2";
      )     ;
      U     "M53.1";
      U     "M76.1";
      U     "M77.7";
      U     "M54.2";
      U     "R3";
      UN    "M79.6";
      UN    "M80.7";
      U(    ;
      L     "R-W Asse Y Spazzolatura".QAttualeAsseY;
      L     "Scambio dati OP".QuotaBaseAsseYSpazz;
      <=D   ;
      )     ;
      =     "M79.4";
NETWORK
TITLE =Asse X Spazzolatura in Movimento verso il Secondo Posizionamento

      U     "M53.1";
      U     "M79.4";
      U(    ;
      ON    "R-W Asse X Spazzolatura".IMEF;
      O(    ;
      L     "R-W Asse X Spazzolatura".QAttualeAsseX;
      L     "Scambio dati OP".Q2AsseXSpazzolatura;
      ==D   ;
      )     ;
      )     ;
      UN    "M79.6";
      UN    "M80.7";
      =     "M79.5";
NETWORK
TITLE =Asse X Spazzolatura Secondo Posizionamento Raggiunto

      U     "M53.1";
      U     "M79.5";
      U     "R-W Asse X Spazzolatura".RLPDR;
      U(    ;
      L     "R-W Asse X Spazzolatura".QAttualeAsseX;
      L     "Scambio dati OP".Q2AsseXSpazzolatura;
      ==D   ;
      )     ;
      S     "M79.6";
      U     "M80.7";
      R     "M79.6";
      NOP   0;
NETWORK
TITLE =Com Aut Start Secondo Posizionamento Asse Z Spazzolatura

      U(    ;
      O     "M20.1";
      O     "M20.2";
      )     ;
      U     "M53.1";
      U     "M76.1";
      U     "M77.7";
      U     "M54.2";
      U     "R3";
      UN    "M80.1";
      UN    "M80.7";
      U(    ;
      L     "R-W Asse Y Spazzolatura".QAttualeAsseY;
      L     "Scambio dati OP".QuotaBaseAsseYSpazz;
      <=D   ;
      )     ;
      =     "M79.7";
NETWORK
TITLE =Asse Z Spazzolatura in Movimento verso il Secondo Posizionamento

      U     "M53.1";
      U     "M79.7";
      U(    ;
      ON    "R-W Asse Z Spazzolatura".IMEF;
      O(    ;
      L     "R-W Asse Z Spazzolatura".QAttualeAsseZ;
      L     "Scambio dati OP".Q2AsseZSpazzolatura;
      ==D   ;
      )     ;
      )     ;
      UN    "M80.1";
      UN    "M80.7";
      =     "M80.0";
NETWORK
TITLE =Asse Z Spazzolatura Secondo Posizionamento Raggiunto

      U     "M53.1";
      U     "M80.0";
      U     "R-W Asse Z Spazzolatura".RLPDR;
      U(    ;
      L     "R-W Asse Z Spazzolatura".QAttualeAsseZ;
      L     "Scambio dati OP".Q2AsseZSpazzolatura;
      ==D   ;
      )     ;
      S     "M80.1";
      U     "M80.7";
      R     "M80.1";
      NOP   0;
NETWORK
TITLE =Com Aut Start Secondo Posizionamento Asse Y Spazzolatura

      U(    ;
      O     "M20.1";
      O     "M20.2";
      )     ;
      U     "M53.1";
      U     "M76.1";
      U     "M77.7";
      U     "M79.6";
      U     "M80.1";
      U     "M54.2";
      U     "R3";
      UN    "M80.4";
      UN    "M80.7";
      =     "M80.2";
NETWORK
TITLE =Asse Y Spazzolatura in Movimento verso il Secondo Posizionamento

      U     "M53.1";
      U     "M80.2";
      U(    ;
      ON    "R-W Asse Y Spazzolatura".IMEF;
      O(    ;
      L     "R-W Asse Y Spazzolatura".QAttualeAsseY;
      L     "Scambio dati OP".Q2AsseYSpazzolatura;
      ==D   ;
      )     ;
      )     ;
      UN    "M80.4";
      UN    "M80.7";
      =     "M80.3";
NETWORK
TITLE =Asse Y Spazzolatura Secondo Posizionamento Raggiunto

      U     "M53.1";
      U     "M80.3";
      U     "R-W Asse Y Spazzolatura".RLPDR;
      U(    ;
      L     "R-W Asse Y Spazzolatura".QAttualeAsseY;
      L     "Scambio dati OP".Q2AsseYSpazzolatura;
      ==D   ;
      )     ;
      S     "M80.4";
      U     "M80.7";
      R     "M80.4";
      NOP   0;
NETWORK
TITLE =Tempo di Spazzolatura Secondo Posizionamento

      U     "M53.1";
      U     "M80.4";
      L     "Scambio dati OP".TempChiPinzaCrimp;
      SE    "T50";
      NOP   0;
      NOP   0;
      NOP   0;
      NOP   0;
NETWORK
TITLE =Com Aut Start Pos Base Asse Y Spazzolatura dopo Seconda Spazz

      U     "M53.1";
      U     "M80.4";
      U     "T50";
      UN    "M80.7";
      =     "M80.5";
NETWORK
TITLE =Asse Y Spazzolatura in Movimento verso Pos Base dopo Secon Spazz

      U     "M53.1";
      U     "M80.5";
      U(    ;
      ON    "R-W Asse Y Spazzolatura".IMEF;
      O(    ;
      L     "R-W Asse Y Spazzolatura".QAttualeAsseY;
      L     "Scambio dati OP".QuotaBaseAsseYSpazz;
      ==D   ;
      )     ;
      )     ;
      UN    "M80.7";
      =     "M80.6";
NETWORK
TITLE =Asse Y Spazzolatura Posizione Base dopo Seconda Spazz Raggiunta

      U     "M53.1";
      U     "M80.6";
      U     "R-W Asse Y Spazzolatura".RLPDR;
      U(    ;
      L     "R-W Asse Y Spazzolatura".QAttualeAsseY;
      L     "Scambio dati OP".QuotaBaseAsseYSpazz;
      ==D   ;
      )     ;
      S     "M80.7";
      UN    "M54.2";
      U     "EV172";
      R     "M80.7";
      NOP   0;
NETWORK
TITLE ======== Terzo Posizionamento Spazzolatura =======

NETWORK
TITLE =Com Aut Start Motore Spazzolatura Terzo Posizonamento

      U     "M20.2";
      U     "M53.1";
      U     "M76.1";
      U     "M80.7";
      U     "M54.2";
      UN    "M83.7";
      U     "M18.0";
      =     "M82.2";
NETWORK
TITLE =Com Aut Start Terzo Posizionamento Asse X Spazzolatura

      U     "M20.2";
      U     "M53.1";
      U     "M76.1";
      U     "M80.7";
      U     "M54.2";
      U     "R3";
      UN    "M82.6";
      UN    "M83.7";
      U(    ;
      L     "R-W Asse Y Spazzolatura".QAttualeAsseY;
      L     "Scambio dati OP".QuotaBaseAsseYSpazz;
      <=D   ;
      )     ;
      =     "M82.4";
NETWORK
TITLE =Asse X Spazzolatura in Movimento verso il Terzo Posizionamento

      U     "M53.1";
      U     "M82.4";
      U(    ;
      ON    "R-W Asse X Spazzolatura".IMEF;
      O(    ;
      L     "R-W Asse X Spazzolatura".QAttualeAsseX;
      L     "Scambio dati OP".Q3AsseXSpazzolatura;
      ==D   ;
      )     ;
      )     ;
      UN    "M82.6";
      UN    "M83.7";
      =     "M82.5";
NETWORK
TITLE =Asse X Spazzolatura Terzo Posizionamento Raggiunto

      U     "M53.1";
      U     "M82.5";
      U     "R-W Asse X Spazzolatura".RLPDR;
      U(    ;
      L     "R-W Asse X Spazzolatura".QAttualeAsseX;
      L     "Scambio dati OP".Q3AsseXSpazzolatura;
      ==D   ;
      )     ;
      S     "M82.6";
      U     "M83.7";
      R     "M82.6";
      NOP   0;
NETWORK
TITLE =Com Aut Start Terzo Posizionamento Asse Z Spazzolatura

      U     "M20.2";
      U     "M53.1";
      U     "M76.1";
      U     "M80.7";
      U     "M54.2";
      U     "R3";
      UN    "M83.1";
      UN    "M83.7";
      U(    ;
      L     "R-W Asse Y Spazzolatura".QAttualeAsseY;
      L     "Scambio dati OP".QuotaBaseAsseYSpazz;
      <=D   ;
      )     ;
      =     "M82.7";
NETWORK
TITLE =Asse Z Spazzolatura in Movimento verso il Terzo Posizionamento

      U     "M53.1";
      U     "M82.7";
      U(    ;
      ON    "R-W Asse Z Spazzolatura".IMEF;
      O(    ;
      L     "R-W Asse Z Spazzolatura".QAttualeAsseZ;
      L     "Scambio dati OP".Q3AsseZSpazzolatura;
      ==D   ;
      )     ;
      )     ;
      UN    "M83.1";
      UN    "M83.7";
      =     "M83.0";
NETWORK
TITLE =Asse Z Spazzolatura Terzo Posizionamento Raggiunto

      U     "M53.1";
      U     "M83.0";
      U     "R-W Asse Z Spazzolatura".RLPDR;
      U(    ;
      L     "R-W Asse Z Spazzolatura".QAttualeAsseZ;
      L     "Scambio dati OP".Q3AsseZSpazzolatura;
      ==D   ;
      )     ;
      S     "M83.1";
      U     "M83.7";
      R     "M83.1";
      NOP   0;
NETWORK
TITLE =Com Aut Start Terzo Posizionamento Asse Y Spazzolatura

      U     "M20.2";
      U     "M53.1";
      U     "M76.1";
      U     "M80.7";
      U     "M82.6";
      U     "M83.1";
      U     "M54.2";
      U     "R3";
      UN    "M83.4";
      UN    "M83.7";
      =     "M83.2";
NETWORK
TITLE =Asse Y Spazzolatura in Movimento verso il Terzo Posizionamento

      U     "M53.1";
      U     "M83.2";
      U(    ;
      ON    "R-W Asse Y Spazzolatura".IMEF;
      O(    ;
      L     "R-W Asse Y Spazzolatura".QAttualeAsseY;
      L     "Scambio dati OP".Q3AsseYSpazzolatura;
      ==D   ;
      )     ;
      )     ;
      UN    "M83.4";
      UN    "M83.7";
      =     "M83.3";
NETWORK
TITLE =Asse Y Spazzolatura Terzo Posizionamento Raggiunto

      U     "M53.1";
      U     "M83.3";
      U     "R-W Asse Y Spazzolatura".RLPDR;
      U(    ;
      L     "R-W Asse Y Spazzolatura".QAttualeAsseY;
      L     "Scambio dati OP".Q3AsseYSpazzolatura;
      ==D   ;
      )     ;
      S     "M83.4";
      U     "M83.7";
      R     "M83.4";
      NOP   0;
NETWORK
TITLE =Tempo di Spazzolatura Terzo Posizionamento

      U     "M53.1";
      U     "M83.4";
      L     "Scambio dati OP".TempChiPinzaCrimp;
      SE    "T51";
      NOP   0;
      NOP   0;
      NOP   0;
      NOP   0;
NETWORK
TITLE =Com Aut Start Pos Base Asse Y Spazzolatura dopo Terza Spazz

      U     "M20.2";
      U     "M53.1";
      U     "M83.4";
      U     "T51";
      UN    "M83.7";
      =     "M83.5";
NETWORK
TITLE =Asse Y Spazzolatura in Movimento verso Pos Base dopo Terza Spazz

      U     "M53.1";
      U     "M83.5";
      U(    ;
      ON    "R-W Asse Y Spazzolatura".IMEF;
      O(    ;
      L     "R-W Asse Y Spazzolatura".QAttualeAsseY;
      L     "Scambio dati OP".QuotaBaseAsseYSpazz;
      ==D   ;
      )     ;
      )     ;
      UN    "M83.7";
      =     "M83.6";
NETWORK
TITLE =Asse Y Spazzolatura Posizione Base dopo Terza Spazz Raggiunta

      U     "M53.1";
      U     "M83.6";
      U     "R-W Asse Y Spazzolatura".RLPDR;
      U(    ;
      L     "R-W Asse Y Spazzolatura".QAttualeAsseY;
      L     "Scambio dati OP".QuotaBaseAsseYSpazz;
      ==D   ;
      )     ;
      S     "M83.7";
      UN    "M54.2";
      U     "EV172";
      R     "M83.7";
      NOP   0;
NETWORK
TITLE ======== Quarto Posizionamento Spazzolatura =======

NETWORK
TITLE =Com Aut Start Motore Spazzolatura Quarto Posizonamento

      U     "M20.2";
      U     "M53.1";
      U     "M76.1";
      U     "M83.7";
      U     "M54.2";
      UN    "M86.7";
      U     "M18.0";
      =     "M85.2";
NETWORK
TITLE =Com Aut Start Quarto Posizionamento Asse X Spazzolatura

      U     "M20.2";
      U     "M53.1";
      U     "M76.1";
      U     "M83.7";
      U     "M54.2";
      U     "R3";
      UN    "M85.6";
      UN    "M86.7";
      U(    ;
      L     "R-W Asse Y Spazzolatura".QAttualeAsseY;
      L     "Scambio dati OP".QuotaBaseAsseYSpazz;
      <=D   ;
      )     ;
      =     "M85.4";
NETWORK
TITLE =Asse X Spazzolatura in Movimento verso il Quarto Posizionamento

      U     "M53.1";
      U     "M85.4";
      U(    ;
      ON    "R-W Asse X Spazzolatura".IMEF;
      O(    ;
      L     "R-W Asse X Spazzolatura".QAttualeAsseX;
      L     "Scambio dati OP".Q4AsseXSpazzolatura;
      ==D   ;
      )     ;
      )     ;
      UN    "M85.6";
      UN    "M86.7";
      =     "M85.5";
NETWORK
TITLE =Asse X Spazzolatura Quarto Posizionamento Raggiunto

      U     "M53.1";
      U     "M85.5";
      U     "R-W Asse X Spazzolatura".RLPDR;
      U(    ;
      L     "R-W Asse X Spazzolatura".QAttualeAsseX;
      L     "Scambio dati OP".Q4AsseXSpazzolatura;
      ==D   ;
      )     ;
      S     "M85.6";
      U     "M86.7";
      R     "M85.6";
      NOP   0;
NETWORK
TITLE =Com Aut Start Quarto Posizionamento Asse Z Spazzolatura

      U     "M20.2";
      U     "M53.1";
      U     "M76.1";
      U     "M83.7";
      U     "M54.2";
      U     "R3";
      UN    "M86.1";
      UN    "M86.7";
      U(    ;
      L     "R-W Asse Y Spazzolatura".QAttualeAsseY;
      L     "Scambio dati OP".QuotaBaseAsseYSpazz;
      <=D   ;
      )     ;
      =     "M85.7";
NETWORK
TITLE =Asse Z Spazzolatura in Movimento verso il Quarto Posizionamento

      U     "M53.1";
      U     "M85.7";
      U(    ;
      ON    "R-W Asse Z Spazzolatura".IMEF;
      O(    ;
      L     "R-W Asse Z Spazzolatura".QAttualeAsseZ;
      L     "Scambio dati OP".Q4AsseZSpazzolatura;
      ==D   ;
      )     ;
      )     ;
      UN    "M86.1";
      UN    "M86.7";
      =     "M86.0";
NETWORK
TITLE =Asse Z Spazzolatura Quarto Posizionamento Raggiunto

      U     "M53.1";
      U     "M86.0";
      U     "R-W Asse Z Spazzolatura".RLPDR;
      U(    ;
      L     "R-W Asse Z Spazzolatura".QAttualeAsseZ;
      L     "Scambio dati OP".Q4AsseZSpazzolatura;
      ==D   ;
      )     ;
      S     "M86.1";
      U     "M86.7";
      R     "M86.1";
      NOP   0;
NETWORK
TITLE =Com Aut Start Quarto Posizionamento Asse Y Spazzolatura

      U     "M20.2";
      U     "M53.1";
      U     "M76.1";
      U     "M83.7";
      U     "M85.6";
      U     "M86.1";
      U     "M54.2";
      U     "R3";
      UN    "M86.4";
      UN    "M86.7";
      =     "M86.2";
NETWORK
TITLE =Asse Y Spazzolatura in Movimento verso il Quarto Posizionamento

      U     "M53.1";
      U     "M86.2";
      U(    ;
      ON    "R-W Asse Y Spazzolatura".IMEF;
      O(    ;
      L     "R-W Asse Y Spazzolatura".QAttualeAsseY;
      L     "Scambio dati OP".Q4AsseYSpazzolatura;
      ==D   ;
      )     ;
      )     ;
      UN    "M86.4";
      UN    "M86.7";
      =     "M86.3";
NETWORK
TITLE =Asse Y Spazzolatura Quarto Posizionamento Raggiunto

      U     "M53.1";
      U     "M86.3";
      U     "R-W Asse Y Spazzolatura".RLPDR;
      U(    ;
      L     "R-W Asse Y Spazzolatura".QAttualeAsseY;
      L     "Scambio dati OP".Q4AsseYSpazzolatura;
      ==D   ;
      )     ;
      S     "M86.4";
      U     "M86.7";
      R     "M86.4";
      NOP   0;
NETWORK
TITLE =Tempo di Spazzolatura Quarto Posizionamento

      U     "M53.1";
      U     "M86.4";
      L     "Scambio dati OP".TempChiPinzaCrimp;
      SE    "T52";
      NOP   0;
      NOP   0;
      NOP   0;
      NOP   0;
NETWORK
TITLE =Com Aut Start Pos Base Asse Y Spazzolatura dopo Quarta Spazz

      U     "M20.2";
      U     "M53.1";
      U     "M86.4";
      U     "T52";
      UN    "M86.7";
      =     "M86.5";
NETWORK
TITLE =Asse Y Spazzolatura in Movimento verso Pos Base dopo Quarta Spaz

      U     "M53.1";
      U     "M86.5";
      U(    ;
      ON    "R-W Asse Y Spazzolatura".IMEF;
      O(    ;
      L     "R-W Asse Y Spazzolatura".QAttualeAsseY;
      L     "Scambio dati OP".QuotaBaseAsseYSpazz;
      ==D   ;
      )     ;
      )     ;
      UN    "M86.7";
      =     "M86.6";
NETWORK
TITLE =Asse Y Spazzolatura Posizione Base dopo Quarta Spazz Raggiunta

      U     "M53.1";
      U     "M86.6";
      U     "R-W Asse Y Spazzolatura".RLPDR;
      U(    ;
      L     "R-W Asse Y Spazzolatura".QAttualeAsseY;
      L     "Scambio dati OP".QuotaBaseAsseYSpazz;
      ==D   ;
      )     ;
      S     "M86.7";
      UN    "M54.2";
      U     "EV172";
      R     "M86.7";
      NOP   0;
NETWORK
TITLE =Fine Ciclo Spazzolatura

      U     "M77.7";
      U     "M80.7";
      U(    ;
      U     "M83.7";
      U     "M86.7";
      O     "M20.1";
      )     ;
      S     "M88.0";
      UN    "M54.2";
      U     "EV172";
      R     "M88.0";
      NOP   0;
NETWORK
TITLE =Com Aut Indietro Bloccaggio Zona Spazzolatura

      U     "M53.1";
      U(    ;
      U     "M54.2";
      U     "M88.0";
      ON    "M54.2";
      O     ;
      UN    "SL254";
      U     "E1.2";
      O     ;
      UN    "SL254";
      U(    ;
      O(    ;
      L     "R-W Asse X Spazzolatura".QAttualeAsseX;
      L     "Scambio dati OP".QuotaBaseAssiXSpazz;
      <=D   ;
      )     ;
      O(    ;
      L     "R-W Asse X Spazzolatura".QAttualeAsseX;
      L     "Scambio dati OP".Q1AsseXSpazzolatura;
      ==D   ;
      )     ;
      )     ;
      U(    ;
      L     "R-W Asse Y Spazzolatura".QAttualeAsseY;
      L     "Scambio dati OP".QuotaBaseAsseYSpazz;
      <=D   ;
      )     ;
      U(    ;
      O(    ;
      L     "R-W Asse Z Spazzolatura".QAttualeAsseZ;
      L     "Scambio dati OP".QuotaBaseAsseZSpazz;
      <=D   ;
      )     ;
      O(    ;
      L     "R-W Asse Z Spazzolatura".QAttualeAsseZ;
      L     "Scambio dati OP".Q1AsseZSpazzolatura;
      ==D   ;
      )     ;
      )     ;
      )     ;
      U     "M17.3";
      =     "M88.1";
NETWORK
TITLE =Com Aut Indietro Fermo Zona Spazzolatura

      U     "M53.1";
      U     "M54.2";
      U(    ;
      O     "M88.0";
      O     ;
      UN    "SL254";
      U     "E1.2";
      O     ;
      UN    "SL254";
      U(    ;
      O(    ;
      L     "R-W Asse X Spazzolatura".QAttualeAsseX;
      L     "Scambio dati OP".QuotaBaseAssiXSpazz;
      <=D   ;
      )     ;
      O(    ;
      L     "R-W Asse X Spazzolatura".QAttualeAsseX;
      L     "Scambio dati OP".Q1AsseXSpazzolatura;
      ==D   ;
      )     ;
      )     ;
      U(    ;
      L     "R-W Asse Y Spazzolatura".QAttualeAsseY;
      L     "Scambio dati OP".QuotaBaseAsseYSpazz;
      <=D   ;
      )     ;
      U(    ;
      O(    ;
      L     "R-W Asse Z Spazzolatura".QAttualeAsseZ;
      L     "Scambio dati OP".QuotaBaseAsseZSpazz;
      <=D   ;
      )     ;
      O(    ;
      L     "R-W Asse Z Spazzolatura".QAttualeAsseZ;
      L     "Scambio dati OP".Q1AsseZSpazzolatura;
      ==D   ;
      )     ;
      )     ;
      )     ;
      U     "M17.5";
      =     "M88.2";
END_FUNCTION

